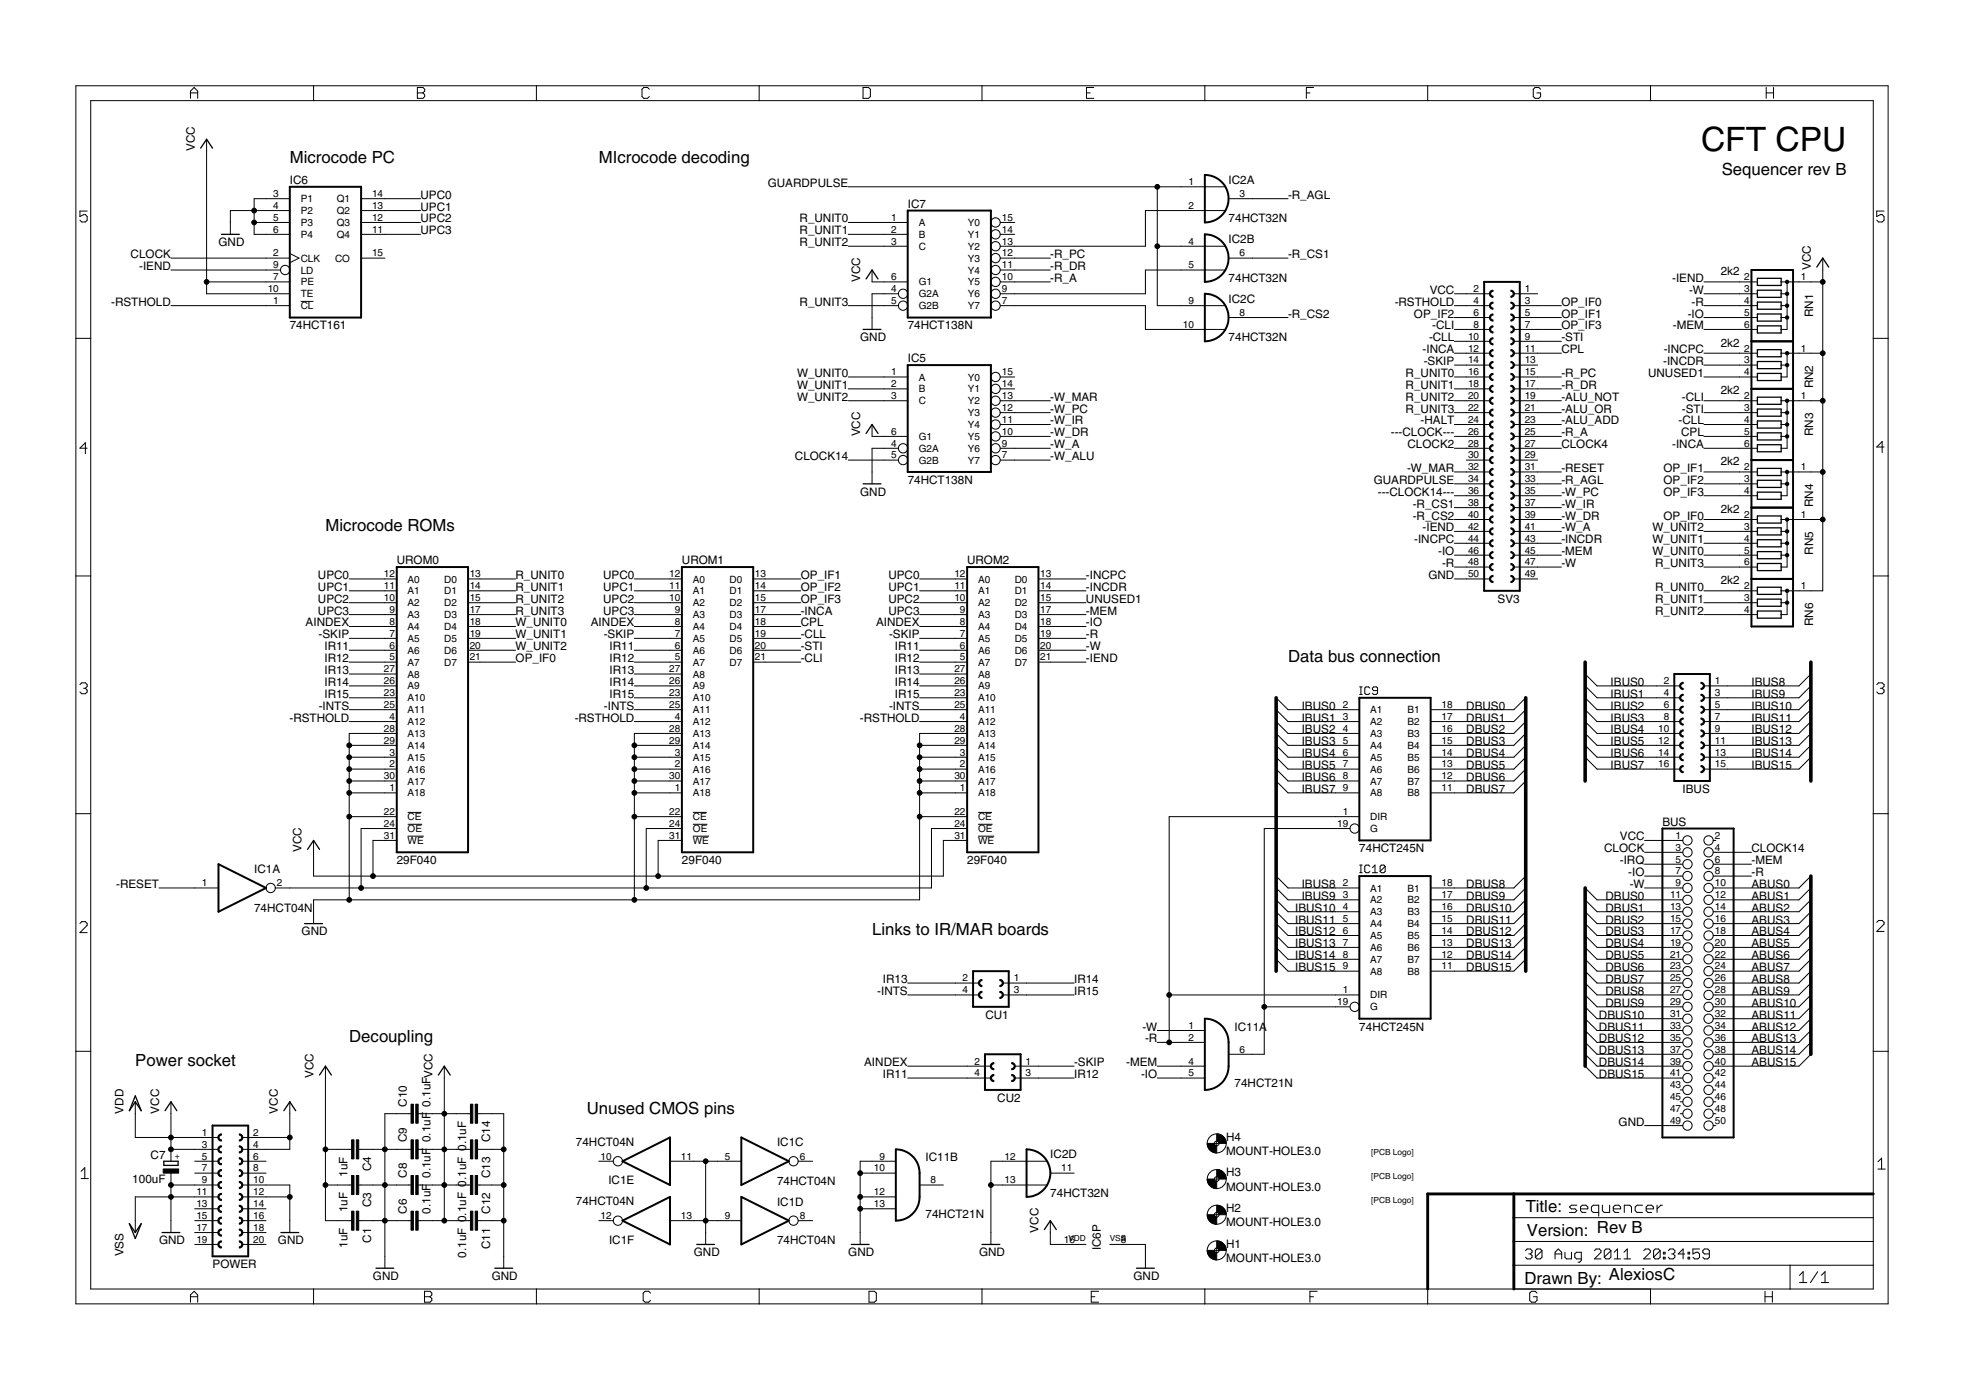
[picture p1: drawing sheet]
<svg xmlns="http://www.w3.org/2000/svg" width="420mm" height="297mm" viewBox="0 0 420 297" stroke-linecap="round" stroke-linejoin="round" font-family="sans-serif">
<defs><g id="words">
<text font-size="7.2" x="363.5" y="32.3">CFT CPU</text>
<g font-size="3.6">
<text x="61.9" y="34.8">Microcode PC</text>
<text x="128" y="34.8">MIcrocode decoding</text>
<text x="368" y="37.4">Sequencer rev B</text>
<text x="69.5" y="113.6">Microcode ROMs</text>
<text x="275.3" y="141.5">Data bus connection</text>
<text x="186.4" y="199.9">Links to IR/MAR boards</text>
<text x="28.9" y="227.8">Power socket</text>
<text x="74.6" y="222.8">Decoupling</text>
<text x="125.4" y="238">Unused CMOS pins</text>
<text x="326.1" y="259.1">Title:</text>
<text x="326.3" y="264.2">Version: Rev B</text>
<text x="325.8" y="274.3">Drawn By: AlexiosC</text>
</g>
<g font-size="2.5">
<text x="41.6" y="32.3" transform="rotate(-90 41.6 32.3)">VCC</text>
<text x="61.9" y="39.3">IC6</text>
<text x="164.1" y="39.9">GUARDPULSE</text>
<text x="262.6" y="39.3">IC2A</text>
<text x="89.9" y="42.5">UPC0</text>
<text x="89.9" y="45">UPC1</text>
<text x="89.9" y="47.5">UPC2</text>
<text x="170.9" y="47.5">R_UNIT0</text>
<text x="194" y="44.4">IC7</text>
<text x="262.6" y="47.5">74HCT32N</text>
<text x="275.3" y="42.5">-R_AGL</text>
<text x="46.7" y="52.6">GND</text>
<text x="89.9" y="50.1">UPC3</text>
<text x="170.9" y="50.1">R_UNIT1</text>
<text x="170.9" y="52.6">R_UNIT2</text>
<text x="262.6" y="52">IC2B</text>
<text x="27.9" y="55.2">CLOCK</text>
<text x="29.7" y="57.7">-IEND</text>
<text x="224.5" y="55.2">-R_PC</text>
<text x="224.5" y="57.7">-R_DR</text>
<text x="275.3" y="55.2">-R_CS1</text>
<text x="367.7" y="58.8">2k2</text>
<text x="387" y="57.7" transform="rotate(-90 387 57.7)">VCC</text>
<text x="23.8" y="65.3">-RSTHOLD</text>
<text x="170.9" y="65.3">R_UNIT3</text>
<text x="183.8" y="60.2" transform="rotate(-90 183.8 60.2)">VCC</text>
<text x="224.5" y="60.2">-R_A</text>
<text x="262.6" y="60.2">74HCT32N</text>
<text x="262.6" y="64.7">IC2C</text>
<text x="298.1" y="65.3">-RSTHOLD</text>
<text x="305.6" y="62.8">VCC</text>
<text x="333.7" y="65.3">OP_IF0</text>
<text x="357.4" y="60.2">-IEND</text>
<text x="361" y="62.8">-W</text>
<text x="361.5" y="65.3">-R</text>
<text x="61.9" y="70.4">74HCT161</text>
<text x="194" y="70.4">74HCT138N</text>
<text x="275.3" y="67.9">-R_CS2</text>
<text x="302.2" y="67.9">OP_IF2</text>
<text x="306.1" y="70.4">-CLI</text>
<text x="333.7" y="67.9">OP_IF1</text>
<text x="333.7" y="70.4">OP_IF3</text>
<text x="357.5" y="70.4">-MEM</text>
<text x="360.7" y="67.9">-IO</text>
<text x="387.5" y="67.8" transform="rotate(-90 387.5 67.8)">RN1</text>
<text x="183.8" y="72.9">GND</text>
<text x="194" y="77.4">IC5</text>
<text x="262.6" y="72.9">74HCT32N</text>
<text x="304" y="75.5">-INCA</text>
<text x="305.4" y="72.9">-CLL</text>
<text x="333.7" y="72.9">-STI</text>
<text x="333.7" y="75.5">CPL</text>
<text x="355.6" y="75.5">-INCPC</text>
<text x="367.7" y="74.1">2k2</text>
<text x="170.3" y="80.6">W_UNIT0</text>
<text x="170.3" y="83.1">W_UNIT1</text>
<text x="300.4" y="80.6">R_UNIT0</text>
<text x="300.4" y="83.1">R_UNIT1</text>
<text x="304.3" y="78">-SKIP</text>
<text x="333.7" y="80.6">-R_PC</text>
<text x="333.7" y="83.1">-R_DR</text>
<text x="352.2" y="80.6">UNUSED1</text>
<text x="355.4" y="78">-INCDR</text>
<text x="387.5" y="83" transform="rotate(-90 387.5 83)">RN2</text>
<text x="170.3" y="85.6">W_UNIT2</text>
<text x="224.5" y="85.6">-W_MAR</text>
<text x="224.5" y="88.2">-W_PC</text>
<text x="300.4" y="85.6">R_UNIT2</text>
<text x="300.4" y="88.2">R_UNIT3</text>
<text x="333.7" y="88.2">-ALU_OR</text>
<text x="333.7" y="85.6">-ALU_NOT</text>
<text x="359.4" y="85.6">-CLI</text>
<text x="359.4" y="88.2">-STI</text>
<text x="367.7" y="84.2">2k2</text>
<text x="183.8" y="93.2" transform="rotate(-90 183.8 93.2)">VCC</text>
<text x="224.5" y="90.7">-W_IR</text>
<text x="224.5" y="93.2">-W_DR</text>
<text x="224.5" y="95.8">-W_A</text>
<text x="297.3" y="93.2">---CLOCK---</text>
<text x="300.8" y="95.8">CLOCK2</text>
<text x="303.6" y="90.7">-HALT</text>
<text x="333.7" y="95.8">CLOCK4</text>
<text x="333.7" y="90.7">-ALU_ADD</text>
<text x="333.7" y="93.2">-R_A</text>
<text x="357.4" y="95.8">-INCA</text>
<text x="358.7" y="90.7">-CLL</text>
<text x="359.3" y="93.2">CPL</text>
<text x="387.5" y="93.2" transform="rotate(-90 387.5 93.2)">RN3</text>
<text x="169.9" y="98.3">CLOCK14</text>
<text x="224.5" y="98.3">-W_ALU</text>
<text x="300.7" y="100.9">-W_MAR</text>
<text x="333.7" y="100.9">-RESET</text>
<text x="355.5" y="100.9">OP_IF1</text>
<text x="367.7" y="99.5">2k2</text>
<text x="183.8" y="105.9">GND</text>
<text x="194" y="103.4">74HCT138N</text>
<text x="293.6" y="103.4">GUARDPULSE</text>
<text x="294.5" y="105.9">---CLOCK14---</text>
<text x="333.7" y="105.9">-W_PC</text>
<text x="333.7" y="103.4">-R_AGL</text>
<text x="355.5" y="103.4">OP_IF2</text>
<text x="355.5" y="105.9">OP_IF3</text>
<text x="301.9" y="108.5">-R_CS1</text>
<text x="301.9" y="111">-R_CS2</text>
<text x="304" y="113.6">-IEND</text>
<text x="333.7" y="108.5">-W_IR</text>
<text x="333.7" y="111">-W_DR</text>
<text x="333.7" y="113.6">-W_A</text>
<text x="353.2" y="113.6">W_UNIT2</text>
<text x="355.5" y="111">OP_IF0</text>
<text x="367.7" y="109.6">2k2</text>
<text x="387.5" y="108.4" transform="rotate(-90 387.5 108.4)">RN4</text>
<text x="302.2" y="116.1">-INCPC</text>
<text x="307.3" y="118.6">-IO</text>
<text x="333.7" y="118.6">-MEM</text>
<text x="333.7" y="116.1">-INCDR</text>
<text x="353.2" y="118.6">W_UNIT0</text>
<text x="353.2" y="116.1">W_UNIT1</text>
<text x="387.5" y="118.6" transform="rotate(-90 387.5 118.6)">RN5</text>
<text x="68" y="123.7">UPC0</text>
<text x="84.8" y="120.5">UROM0</text>
<text x="110.2" y="123.7">R_UNIT0</text>
<text x="128.9" y="123.7">UPC0</text>
<text x="145.7" y="120.5">UROM1</text>
<text x="171.1" y="123.7">OP_IF1</text>
<text x="189.9" y="123.7">UPC0</text>
<text x="206.7" y="120.5">UROM2</text>
<text x="232.1" y="123.7">-INCPC</text>
<text x="305.3" y="123.7">GND</text>
<text x="308.2" y="121.2">-R</text>
<text x="333.7" y="121.2">-W</text>
<text x="353.7" y="121.2">R_UNIT3</text>
<text x="367.7" y="124.9">2k2</text>
<text x="68" y="126.3">UPC1</text>
<text x="68" y="128.8">UPC2</text>
<text x="68" y="131.3">UPC3</text>
<text x="110.2" y="126.3">R_UNIT1</text>
<text x="110.2" y="128.8">R_UNIT2</text>
<text x="110.2" y="131.3">R_UNIT3</text>
<text x="128.9" y="126.3">UPC1</text>
<text x="128.9" y="128.8">UPC2</text>
<text x="128.9" y="131.3">UPC3</text>
<text x="171.1" y="131.3">-INCA</text>
<text x="171.1" y="126.3">OP_IF2</text>
<text x="171.1" y="128.8">OP_IF3</text>
<text x="189.9" y="126.3">UPC1</text>
<text x="189.9" y="128.8">UPC2</text>
<text x="189.9" y="131.3">UPC3</text>
<text x="232.1" y="131.3">-MEM</text>
<text x="232.1" y="126.3">-INCDR</text>
<text x="232.1" y="128.8">UNUSED1</text>
<text x="320" y="128.8">SV3</text>
<text x="353.7" y="126.3">R_UNIT0</text>
<text x="353.7" y="128.8">R_UNIT1</text>
<text x="353.7" y="131.3">R_UNIT2</text>
<text x="65.3" y="133.9">AINDEX</text>
<text x="68.1" y="136.4">-SKIP</text>
<text x="110.2" y="133.9">W_UNIT0</text>
<text x="110.2" y="136.4">W_UNIT1</text>
<text x="126.3" y="133.9">AINDEX</text>
<text x="129" y="136.4">-SKIP</text>
<text x="171.1" y="136.4">-CLL</text>
<text x="171.1" y="133.9">CPL</text>
<text x="187.2" y="133.9">AINDEX</text>
<text x="190" y="136.4">-SKIP</text>
<text x="232.1" y="133.9">-IO</text>
<text x="232.1" y="136.4">-R</text>
<text x="387.5" y="133.8" transform="rotate(-90 387.5 133.8)">RN6</text>
<text x="69.3" y="139">IR11</text>
<text x="69.3" y="141.5">IR12</text>
<text x="110.2" y="139">W_UNIT2</text>
<text x="110.2" y="141.5">OP_IF0</text>
<text x="130.3" y="139">IR11</text>
<text x="130.3" y="141.5">IR12</text>
<text x="171.1" y="141.5">-CLI</text>
<text x="171.1" y="139">-STI</text>
<text x="191.2" y="139">IR11</text>
<text x="191.2" y="141.5">IR12</text>
<text x="232.1" y="141.5">-IEND</text>
<text x="232.1" y="139">-W</text>
<text x="69.3" y="144">IR13</text>
<text x="69.3" y="146.6">IR14</text>
<text x="69.3" y="149.1">IR15</text>
<text x="130.3" y="144">IR13</text>
<text x="130.3" y="146.6">IR14</text>
<text x="130.3" y="149.1">IR15</text>
<text x="191.2" y="144">IR13</text>
<text x="191.2" y="146.6">IR14</text>
<text x="191.2" y="149.1">IR15</text>
<text x="344.2" y="146.6">IBUS0</text>
<text x="344.2" y="149.1">IBUS1</text>
<text x="374.3" y="146.6">IBUS8</text>
<text x="374.3" y="149.1">IBUS9</text>
<text x="61.9" y="154.2">-RSTHOLD</text>
<text x="68.1" y="151.7">-INTS</text>
<text x="122.8" y="154.2">-RSTHOLD</text>
<text x="129.1" y="151.7">-INTS</text>
<text x="183.8" y="154.2">-RSTHOLD</text>
<text x="190" y="151.7">-INTS</text>
<text x="278.2" y="151.7">IBUS0</text>
<text x="278.2" y="154.2">IBUS1</text>
<text x="313.4" y="151.7">DBUS0</text>
<text x="313.4" y="154.2">DBUS1</text>
<text x="344.2" y="151.7">IBUS2</text>
<text x="344.2" y="154.2">IBUS3</text>
<text x="374.3" y="151.7">IBUS10</text>
<text x="374.3" y="154.2">IBUS11</text>
<text x="278.2" y="156.7">IBUS2</text>
<text x="278.2" y="159.3">IBUS3</text>
<text x="278.2" y="161.8">IBUS4</text>
<text x="313.4" y="156.7">DBUS2</text>
<text x="313.4" y="159.3">DBUS3</text>
<text x="313.4" y="161.8">DBUS4</text>
<text x="344.2" y="156.7">IBUS4</text>
<text x="344.2" y="159.3">IBUS5</text>
<text x="344.2" y="161.8">IBUS6</text>
<text x="374.3" y="156.7">IBUS12</text>
<text x="374.3" y="159.3">IBUS13</text>
<text x="374.3" y="161.8">IBUS14</text>
<text x="278.2" y="164.4">IBUS5</text>
<text x="278.2" y="166.9">IBUS6</text>
<text x="313.4" y="164.4">DBUS5</text>
<text x="313.4" y="166.9">DBUS6</text>
<text x="344.2" y="164.4">IBUS7</text>
<text x="374.3" y="164.4">IBUS15</text>
<text x="278.2" y="169.4">IBUS7</text>
<text x="313.4" y="169.4">DBUS7</text>
<text x="359.6" y="169.4">IBUS</text>
<text x="346.2" y="179.6">VCC</text>
<text x="355.3" y="176.4">BUS</text>
<text x="64.5" y="182.1" transform="rotate(-90 64.5 182.1)">VCC</text>
<text x="84.8" y="184.7">29F040</text>
<text x="145.7" y="184.7">29F040</text>
<text x="206.7" y="184.7">29F040</text>
<text x="290.5" y="182.1">74HCT245N</text>
<text x="342.8" y="182.1">CLOCK</text>
<text x="346.2" y="184.7">-IRQ</text>
<text x="374.3" y="182.1">CLOCK14</text>
<text x="374.3" y="184.7">-MEM</text>
<text x="24.8" y="189.8">-RESET</text>
<text x="54.3" y="186.6">IC1A</text>
<text x="278.2" y="189.8">IBUS8</text>
<text x="313.4" y="189.8">DBUS8</text>
<text x="348" y="187.2">-IO</text>
<text x="348.3" y="189.8">-W</text>
<text x="374.3" y="187.2">-R</text>
<text x="374.3" y="189.8">ABUS0</text>
<text x="54.3" y="194.8">74HCT04N</text>
<text x="276.8" y="194.8">IBUS10</text>
<text x="276.8" y="197.4">IBUS11</text>
<text x="278.2" y="192.3">IBUS9</text>
<text x="313.4" y="192.3">DBUS9</text>
<text x="313.4" y="194.8">DBUS10</text>
<text x="313.4" y="197.4">DBUS11</text>
<text x="343.1" y="192.3">DBUS0</text>
<text x="343.1" y="194.8">DBUS1</text>
<text x="343.1" y="197.4">DBUS2</text>
<text x="374.3" y="192.3">ABUS1</text>
<text x="374.3" y="194.8">ABUS2</text>
<text x="374.3" y="197.4">ABUS3</text>
<text x="64.5" y="199.9">GND</text>
<text x="276.8" y="199.9">IBUS12</text>
<text x="276.8" y="202.4">IBUS13</text>
<text x="313.4" y="199.9">DBUS12</text>
<text x="313.4" y="202.4">DBUS13</text>
<text x="343.1" y="199.9">DBUS3</text>
<text x="343.1" y="202.4">DBUS4</text>
<text x="374.3" y="199.9">ABUS4</text>
<text x="374.3" y="202.4">ABUS5</text>
<text x="276.8" y="205">IBUS14</text>
<text x="276.8" y="207.5">IBUS15</text>
<text x="313.4" y="205">DBUS14</text>
<text x="313.4" y="207.5">DBUS15</text>
<text x="343.1" y="205">DBUS5</text>
<text x="343.1" y="207.5">DBUS6</text>
<text x="374.3" y="205">ABUS6</text>
<text x="374.3" y="207.5">ABUS7</text>
<text x="187.5" y="212.6">-INTS</text>
<text x="188.7" y="210.1">IR13</text>
<text x="229.5" y="210.1">IR14</text>
<text x="229.5" y="212.6">IR15</text>
<text x="343.1" y="210.1">DBUS7</text>
<text x="343.1" y="212.6">DBUS8</text>
<text x="343.1" y="215.1">DBUS9</text>
<text x="374.3" y="210.1">ABUS8</text>
<text x="374.3" y="212.6">ABUS9</text>
<text x="374.3" y="215.1">ABUS10</text>
<text x="210.6" y="217.7">CU1</text>
<text x="244.2" y="220.2">-W</text>
<text x="263.8" y="220.2">IC11A</text>
<text x="290.5" y="220.2">74HCT245N</text>
<text x="341.7" y="217.7">DBUS10</text>
<text x="341.7" y="220.2">DBUS11</text>
<text x="374.3" y="217.7">ABUS11</text>
<text x="374.3" y="220.2">ABUS12</text>
<text x="184.7" y="227.8">AINDEX</text>
<text x="229.5" y="227.8">-SKIP</text>
<text x="240.7" y="227.8">-MEM</text>
<text x="244.7" y="222.8">-R</text>
<text x="341.7" y="222.8">DBUS12</text>
<text x="341.7" y="225.3">DBUS13</text>
<text x="341.7" y="227.8">DBUS14</text>
<text x="374.3" y="225.3">ABUS14</text>
<text x="374.3" y="227.8">ABUS15</text>
<text x="374.3" y="222.8">ABUS13</text>
<text x="67" y="230.4" transform="rotate(-90 67 230.4)">VCC</text>
<text x="188.7" y="230.4">IR11</text>
<text x="229.5" y="230.4">IR12</text>
<text x="243.9" y="230.4">-IO</text>
<text x="263.8" y="232.3">74HCT21N</text>
<text x="341.7" y="230.4">DBUS15</text>
<text x="26.4" y="238" transform="rotate(-90 26.4 238)">VDD</text>
<text x="34" y="238" transform="rotate(-90 34 238)">VCC</text>
<text x="59.4" y="238" transform="rotate(-90 59.4 238)">VCC</text>
<text x="86.9" y="236.5" transform="rotate(-90 86.9 236.5)">C10</text>
<text x="92" y="236.5" transform="rotate(-90 92 236.5)">0.1uFVCC</text>
<text x="213.1" y="235.5">CU2</text>
<text x="86.9" y="244.1" transform="rotate(-90 86.9 244.1)">C9</text>
<text x="92" y="244.1" transform="rotate(-90 92 244.1)">0.1uF</text>
<text x="104.7" y="244.1" transform="rotate(-90 104.7 244.1)">C14</text>
<text x="123.1" y="244.9">74HCT04N</text>
<text x="166.1" y="245">IC1C</text>
<text x="262.1" y="243.8">H4</text>
<text x="345.9" y="240.5">GND</text>
<text x="32.2" y="247.7">C7</text>
<text x="74.2" y="251.5" transform="rotate(-90 74.2 251.5)">1uF</text>
<text x="79.3" y="250.3" transform="rotate(-90 79.3 250.3)">C4</text>
<text x="86.9" y="251.7" transform="rotate(-90 86.9 251.7)">C8</text>
<text x="92" y="251.7" transform="rotate(-90 92 251.7)">0.1uF</text>
<text x="104.7" y="251.7" transform="rotate(-90 104.7 251.7)">C13</text>
<text x="197.8" y="248.2">IC11B</text>
<text x="224.5" y="247.5">IC2D</text>
<text x="262.1" y="246.8">MOUNT-HOLE3.0</text>
<text x="262.1" y="251.4">H3</text>
<text x="28.3" y="252.8">100uF</text>
<text x="79.3" y="258" transform="rotate(-90 79.3 258)">C3</text>
<text x="123.1" y="257.6">74HCT04N</text>
<text x="130" y="253.1">IC1E</text>
<text x="166.1" y="253.2">74HCT04N</text>
<text x="166.1" y="257.7">IC1D</text>
<text x="224.5" y="255.8">74HCT32N</text>
<text x="262.1" y="254.4">MOUNT-HOLE3.0</text>
<text x="74.2" y="259.1" transform="rotate(-90 74.2 259.1)">1uF</text>
<text x="86.9" y="259.3" transform="rotate(-90 86.9 259.3)">C6</text>
<text x="92" y="259.3" transform="rotate(-90 92 259.3)">0.1uF</text>
<text x="104.7" y="259.4" transform="rotate(-90 104.7 259.4)">C12</text>
<text x="197.8" y="260.2">74HCT21N</text>
<text x="221.9" y="263.4" transform="rotate(-90 221.9 263.4)">VCC</text>
<text x="262.1" y="262">MOUNT-HOLE3.0</text>
<text x="262.1" y="259">H2</text>
<text x="26.4" y="268.5" transform="rotate(-90 26.4 268.5)">VSS</text>
<text x="34" y="265.9">GND</text>
<text x="59.4" y="265.9">GND</text>
<text x="74.2" y="266.7" transform="rotate(-90 74.2 266.7)">1uF</text>
<text x="79.3" y="265.6" transform="rotate(-90 79.3 265.6)">C1</text>
<text x="99.6" y="268.8" transform="rotate(-90 99.6 268.8)">0.1uF 0.1uF 0.1uF 0.1uF</text>
<text x="104.7" y="267" transform="rotate(-90 104.7 267)">C11</text>
<text x="130.2" y="265.8">IC1F</text>
<text x="148.3" y="268.5">GND</text>
<text x="166.1" y="265.9">74HCT04N</text>
<text x="181.3" y="268.5">GND</text>
<text x="209.2" y="268.5">GND</text>
<text x="235.3" y="267.2" transform="rotate(-90 235.3 267.2)">IC6P</text>
<text x="262.1" y="269.7">MOUNT-HOLE3.0</text>
<text x="262.1" y="266.6">H1</text>
<text x="45.4" y="271">POWER</text>
<text x="79.7" y="273.6">GND</text>
<text x="105.1" y="273.6">GND</text>
<text x="242.2" y="273.6">GND</text>
</g>
<g font-size="2.1">
<text x="254" y="39.6">1</text>
<text x="58.4" y="42.1">3</text>
<text x="58.4" y="44.6">4</text>
<text x="58.4" y="47.2">5</text>
<text x="64.3" y="43.2">P1</text>
<text x="64.3" y="45.8">P2</text>
<text x="72" y="45.8">Q2</text>
<text x="72" y="43.2">Q1</text>
<text x="79.5" y="47.2">12</text>
<text x="79.5" y="44.6">13</text>
<text x="79.5" y="42.1">14</text>
<text x="190.5" y="47.2">1</text>
<text x="214.1" y="47.2">15</text>
<text x="254" y="44.6">2</text>
<text x="264.9" y="42.1">3</text>
<text x="58.4" y="49.7">6</text>
<text x="64.3" y="48.3">P3</text>
<text x="64.3" y="50.8">P4</text>
<text x="72" y="50.8">Q4</text>
<text x="72" y="48.3">Q3</text>
<text x="79.5" y="49.7">11</text>
<text x="190.5" y="49.7">2</text>
<text x="190.5" y="52.3">3</text>
<text x="196.3" y="48.3">A</text>
<text x="196.3" y="50.8">B</text>
<text x="196.3" y="53.4">C</text>
<text x="206.8" y="53.4">Y2</text>
<text x="206.8" y="50.8">Y1</text>
<text x="206.8" y="48.3">Y0</text>
<text x="214.1" y="52.3">13</text>
<text x="214.1" y="49.7">14</text>
<text x="254" y="52.3">4</text>
<text x="58.4" y="54.8">2</text>
<text x="58.4" y="59.9">7</text>
<text x="58.4" y="57.3">9</text>
<text x="64.3" y="55.9">CLK</text>
<text x="64.3" y="58.5">LD</text>
<text x="71.6" y="55.9">CO</text>
<text x="79.5" y="54.8">15</text>
<text x="190.5" y="59.9">6</text>
<text x="206.8" y="58.5">Y4</text>
<text x="206.8" y="55.9">Y3</text>
<text x="214.1" y="59.9">10</text>
<text x="214.1" y="57.3">11</text>
<text x="214.1" y="54.8">12</text>
<text x="254" y="57.3">5</text>
<text x="264.9" y="54.8">6</text>
<text x="372.8" y="59.9">2</text>
<text x="384.8" y="59.9">1</text>
<text x="57.2" y="62.4">10</text>
<text x="58.4" y="65">1</text>
<text x="64.3" y="61">PE</text>
<text x="64.3" y="63.5">TE</text>
<text x="190.5" y="62.4">4</text>
<text x="190.5" y="65">5</text>
<text x="196.3" y="63.5">G2A</text>
<text x="196.3" y="61">G1</text>
<text x="206.8" y="63.5">Y6</text>
<text x="206.8" y="61">Y5</text>
<text x="214.1" y="65">7</text>
<text x="214.1" y="62.4">9</text>
<text x="254" y="65">9</text>
<text x="314.9" y="62.4">2</text>
<text x="314.9" y="65">4</text>
<text x="325.9" y="62.4">1</text>
<text x="325.9" y="65">3</text>
<text x="372.8" y="62.4">3</text>
<text x="372.8" y="65">4</text>
<text x="64.3" y="66.1">CL</text>
<text x="196.3" y="66.1">G2B</text>
<text x="206.8" y="66.1">Y7</text>
<text x="252.8" y="70">10</text>
<text x="264.9" y="67.5">8</text>
<text x="314.9" y="67.5">6</text>
<text x="314.9" y="70">8</text>
<text x="325.9" y="67.5">5</text>
<text x="325.9" y="70">7</text>
<text x="372.8" y="67.5">5</text>
<text x="372.8" y="70">6</text>
<text x="313.7" y="72.6">10</text>
<text x="313.7" y="75.1">12</text>
<text x="313.7" y="77.7">14</text>
<text x="325.9" y="72.6">9</text>
<text x="325.9" y="75.1">11</text>
<text x="325.9" y="77.7">13</text>
<text x="372.8" y="75.1">2</text>
<text x="372.8" y="77.7">3</text>
<text x="384.8" y="75.1">1</text>
<text x="190.5" y="80.2">1</text>
<text x="190.5" y="82.7">2</text>
<text x="196.3" y="81.3">A</text>
<text x="196.3" y="83.9">B</text>
<text x="206.8" y="83.9">Y1</text>
<text x="206.8" y="81.3">Y0</text>
<text x="214.1" y="82.7">14</text>
<text x="214.1" y="80.2">15</text>
<text x="313.7" y="80.2">16</text>
<text x="313.7" y="82.7">18</text>
<text x="325.9" y="80.2">15</text>
<text x="325.9" y="82.7">17</text>
<text x="372.8" y="80.2">4</text>
<text x="190.5" y="85.3">3</text>
<text x="196.3" y="86.4">C</text>
<text x="206.8" y="88.9">Y3</text>
<text x="206.8" y="86.4">Y2</text>
<text x="214.1" y="87.8">12</text>
<text x="214.1" y="85.3">13</text>
<text x="313.7" y="85.3">20</text>
<text x="313.7" y="87.8">22</text>
<text x="325.9" y="85.3">19</text>
<text x="325.9" y="87.8">21</text>
<text x="372.8" y="85.3">2</text>
<text x="372.8" y="87.8">3</text>
<text x="384.8" y="85.3">1</text>
<text x="190.5" y="95.4">4</text>
<text x="190.5" y="92.9">6</text>
<text x="196.3" y="94">G1</text>
<text x="206.8" y="94">Y5</text>
<text x="206.8" y="91.5">Y4</text>
<text x="214.1" y="95.4">9</text>
<text x="214.1" y="92.9">10</text>
<text x="214.1" y="90.4">11</text>
<text x="313.7" y="90.4">24</text>
<text x="313.7" y="92.9">26</text>
<text x="313.7" y="95.4">28</text>
<text x="325.9" y="90.4">23</text>
<text x="325.9" y="92.9">25</text>
<text x="325.9" y="95.4">27</text>
<text x="372.8" y="90.4">4</text>
<text x="372.8" y="92.9">5</text>
<text x="372.8" y="95.4">6</text>
<text x="190.5" y="98">5</text>
<text x="196.3" y="96.5">G2A</text>
<text x="196.3" y="99.1">G2B</text>
<text x="206.8" y="99.1">Y7</text>
<text x="206.8" y="96.6">Y6</text>
<text x="214.1" y="98">7</text>
<text x="313.7" y="98">30</text>
<text x="313.7" y="100.5">32</text>
<text x="325.9" y="98">29</text>
<text x="325.9" y="100.5">31</text>
<text x="372.8" y="100.5">2</text>
<text x="384.8" y="100.5">1</text>
<text x="313.7" y="103.1">34</text>
<text x="313.7" y="105.6">36</text>
<text x="325.9" y="103.1">33</text>
<text x="325.9" y="105.6">35</text>
<text x="372.8" y="103.1">3</text>
<text x="372.8" y="105.6">4</text>
<text x="313.7" y="108.1">38</text>
<text x="313.7" y="110.7">40</text>
<text x="313.7" y="113.2">42</text>
<text x="325.9" y="108.1">37</text>
<text x="325.9" y="110.7">39</text>
<text x="325.9" y="113.2">41</text>
<text x="372.8" y="110.7">2</text>
<text x="372.8" y="113.2">3</text>
<text x="384.8" y="110.7">1</text>
<text x="313.7" y="115.7">44</text>
<text x="313.7" y="118.3">46</text>
<text x="325.9" y="115.7">43</text>
<text x="325.9" y="118.3">45</text>
<text x="372.8" y="115.7">4</text>
<text x="372.8" y="118.3">5</text>
<text x="82.1" y="125.9">11</text>
<text x="82.1" y="123.4">12</text>
<text x="87.1" y="124.5">A0</text>
<text x="95" y="124.5">D0</text>
<text x="100.4" y="123.4">13</text>
<text x="100.4" y="125.9">14</text>
<text x="143" y="125.9">11</text>
<text x="143" y="123.4">12</text>
<text x="148.1" y="124.5">A0</text>
<text x="155.9" y="124.5">D0</text>
<text x="161.3" y="123.4">13</text>
<text x="161.3" y="125.9">14</text>
<text x="204" y="125.9">11</text>
<text x="204" y="123.4">12</text>
<text x="209" y="124.5">A0</text>
<text x="216.9" y="124.5">D0</text>
<text x="222.3" y="123.4">13</text>
<text x="222.3" y="125.9">14</text>
<text x="313.7" y="120.8">48</text>
<text x="313.7" y="123.4">50</text>
<text x="325.9" y="120.8">47</text>
<text x="325.9" y="123.4">49</text>
<text x="372.8" y="120.8">6</text>
<text x="372.8" y="125.9">2</text>
<text x="384.8" y="125.9">1</text>
<text x="82.1" y="128.4">10</text>
<text x="83.2" y="131">9</text>
<text x="87.1" y="129.6">A2</text>
<text x="87.1" y="127">A1</text>
<text x="95" y="127">D1</text>
<text x="95" y="129.6">D2</text>
<text x="100.4" y="128.4">15</text>
<text x="100.4" y="131">17</text>
<text x="143" y="128.4">10</text>
<text x="144.2" y="131">9</text>
<text x="148.1" y="129.6">A2</text>
<text x="148.1" y="127">A1</text>
<text x="155.9" y="127">D1</text>
<text x="155.9" y="129.6">D2</text>
<text x="161.3" y="128.4">15</text>
<text x="161.3" y="131">17</text>
<text x="204" y="128.4">10</text>
<text x="205.2" y="131">9</text>
<text x="209" y="129.6">A2</text>
<text x="209" y="127">A1</text>
<text x="216.9" y="127">D1</text>
<text x="216.9" y="129.6">D2</text>
<text x="222.3" y="128.4">15</text>
<text x="222.3" y="131">17</text>
<text x="372.8" y="128.4">3</text>
<text x="372.8" y="131">4</text>
<text x="83.2" y="136.1">7</text>
<text x="83.2" y="133.5">8</text>
<text x="87.1" y="137.2">A5</text>
<text x="87.1" y="134.6">A4</text>
<text x="87.1" y="132.1">A3</text>
<text x="95" y="132.1">D3</text>
<text x="95" y="134.6">D4</text>
<text x="95" y="137.2">D5</text>
<text x="100.4" y="133.5">18</text>
<text x="100.4" y="136.1">19</text>
<text x="144.2" y="136.1">7</text>
<text x="144.2" y="133.5">8</text>
<text x="148.1" y="137.2">A5</text>
<text x="148.1" y="134.6">A4</text>
<text x="148.1" y="132.1">A3</text>
<text x="155.9" y="132.1">D3</text>
<text x="155.9" y="134.6">D4</text>
<text x="155.9" y="137.2">D5</text>
<text x="161.3" y="133.5">18</text>
<text x="161.3" y="136.1">19</text>
<text x="205.2" y="136.1">7</text>
<text x="205.2" y="133.5">8</text>
<text x="209" y="137.2">A5</text>
<text x="209" y="134.6">A4</text>
<text x="209" y="132.1">A3</text>
<text x="216.9" y="132.1">D3</text>
<text x="216.9" y="134.6">D4</text>
<text x="216.9" y="137.2">D5</text>
<text x="222.3" y="133.5">18</text>
<text x="222.3" y="136.1">19</text>
<text x="82.1" y="143.7">27</text>
<text x="83.2" y="141.1">5</text>
<text x="83.2" y="138.6">6</text>
<text x="87.1" y="142.3">A7</text>
<text x="87.1" y="139.7">A6</text>
<text x="95" y="139.7">D6</text>
<text x="95" y="142.3">D7</text>
<text x="100.4" y="138.6">20</text>
<text x="100.4" y="141.1">21</text>
<text x="143" y="143.7">27</text>
<text x="144.2" y="141.1">5</text>
<text x="144.2" y="138.6">6</text>
<text x="148.1" y="142.3">A7</text>
<text x="148.1" y="139.7">A6</text>
<text x="155.9" y="139.7">D6</text>
<text x="155.9" y="142.3">D7</text>
<text x="161.3" y="138.6">20</text>
<text x="161.3" y="141.1">21</text>
<text x="204" y="143.7">27</text>
<text x="205.2" y="141.1">5</text>
<text x="205.2" y="138.6">6</text>
<text x="209" y="142.3">A7</text>
<text x="209" y="139.7">A6</text>
<text x="216.9" y="139.7">D6</text>
<text x="216.9" y="142.3">D7</text>
<text x="222.3" y="138.6">20</text>
<text x="222.3" y="141.1">21</text>
<text x="82.1" y="148.8">23</text>
<text x="82.1" y="146.2">26</text>
<text x="87.1" y="149.9">A10</text>
<text x="87.1" y="147.3">A9</text>
<text x="87.1" y="144.8">A8</text>
<text x="143" y="148.8">23</text>
<text x="143" y="146.2">26</text>
<text x="148.1" y="149.9">A10</text>
<text x="148.1" y="147.3">A9</text>
<text x="148.1" y="144.8">A8</text>
<text x="204" y="148.8">23</text>
<text x="204" y="146.2">26</text>
<text x="209" y="149.9">A10</text>
<text x="209" y="147.3">A9</text>
<text x="209" y="144.8">A8</text>
<text x="355.6" y="146.2">2</text>
<text x="355.6" y="148.8">4</text>
<text x="366.5" y="146.2">1</text>
<text x="366.5" y="148.8">3</text>
<text x="82.1" y="151.3">25</text>
<text x="83.2" y="153.8">4</text>
<text x="87.1" y="155">A12</text>
<text x="87.1" y="152.4">A11</text>
<text x="143" y="151.3">25</text>
<text x="144.2" y="153.8">4</text>
<text x="148.1" y="155">A12</text>
<text x="148.1" y="152.4">A11</text>
<text x="204" y="151.3">25</text>
<text x="205.2" y="153.8">4</text>
<text x="209" y="155">A12</text>
<text x="209" y="152.4">A11</text>
<text x="287" y="151.3">2</text>
<text x="287" y="153.8">3</text>
<text x="292.8" y="152.4">A1</text>
<text x="292.8" y="155">A2</text>
<text x="300.8" y="155">B2</text>
<text x="300.8" y="152.4">B1</text>
<text x="308.1" y="153.8">17</text>
<text x="308.1" y="151.3">18</text>
<text x="355.6" y="151.3">6</text>
<text x="355.6" y="153.8">8</text>
<text x="366.5" y="151.3">5</text>
<text x="366.5" y="153.8">7</text>
<text x="82.1" y="156.4">28</text>
<text x="82.1" y="158.9">29</text>
<text x="83.2" y="161.5">3</text>
<text x="87.1" y="157.5">A13</text>
<text x="87.1" y="160">A14</text>
<text x="143" y="156.4">28</text>
<text x="143" y="158.9">29</text>
<text x="144.2" y="161.5">3</text>
<text x="148.1" y="157.5">A13</text>
<text x="148.1" y="160">A14</text>
<text x="204" y="156.4">28</text>
<text x="204" y="158.9">29</text>
<text x="205.2" y="161.5">3</text>
<text x="209" y="157.5">A13</text>
<text x="209" y="160">A14</text>
<text x="287" y="156.4">4</text>
<text x="287" y="158.9">5</text>
<text x="287" y="161.5">6</text>
<text x="292.8" y="157.5">A3</text>
<text x="292.8" y="160">A4</text>
<text x="300.8" y="160">B4</text>
<text x="300.8" y="157.5">B3</text>
<text x="308.1" y="161.5">14</text>
<text x="308.1" y="158.9">15</text>
<text x="308.1" y="156.4">16</text>
<text x="354.4" y="156.4">10</text>
<text x="354.4" y="158.9">12</text>
<text x="354.4" y="161.5">14</text>
<text x="366.5" y="156.4">9</text>
<text x="366.5" y="158.9">11</text>
<text x="366.5" y="161.5">13</text>
<text x="82.1" y="166.5">30</text>
<text x="83.2" y="164">2</text>
<text x="87.1" y="162.6">A15</text>
<text x="87.1" y="165.1">A16</text>
<text x="87.1" y="167.7">A17</text>
<text x="143" y="166.5">30</text>
<text x="144.2" y="164">2</text>
<text x="148.1" y="162.6">A15</text>
<text x="148.1" y="165.1">A16</text>
<text x="148.1" y="167.7">A17</text>
<text x="204" y="166.5">30</text>
<text x="205.2" y="164">2</text>
<text x="209" y="162.6">A15</text>
<text x="209" y="165.1">A16</text>
<text x="209" y="167.7">A17</text>
<text x="287" y="164">7</text>
<text x="287" y="166.5">8</text>
<text x="292.8" y="162.6">A5</text>
<text x="292.8" y="165.1">A6</text>
<text x="292.8" y="167.7">A7</text>
<text x="300.8" y="167.7">B7</text>
<text x="300.8" y="165.1">B6</text>
<text x="300.8" y="162.6">B5</text>
<text x="308.1" y="166.5">12</text>
<text x="308.1" y="164">13</text>
<text x="354.4" y="164">16</text>
<text x="366.5" y="164">15</text>
<text x="83.2" y="169.1">1</text>
<text x="87.1" y="170.2">A18</text>
<text x="144.2" y="169.1">1</text>
<text x="148.1" y="170.2">A18</text>
<text x="205.2" y="169.1">1</text>
<text x="209" y="170.2">A18</text>
<text x="287" y="169.1">9</text>
<text x="292.8" y="170.2">A8</text>
<text x="300.8" y="170.2">B8</text>
<text x="308.1" y="169.1">11</text>
<text x="82.1" y="179.2">31</text>
<text x="82.1" y="174.2">22</text>
<text x="82.1" y="176.7">24</text>
<text x="87.1" y="175.3">CE</text>
<text x="87.1" y="177.8">OE</text>
<text x="143" y="179.2">31</text>
<text x="143" y="174.2">22</text>
<text x="143" y="176.7">24</text>
<text x="148.1" y="175.3">CE</text>
<text x="148.1" y="177.8">OE</text>
<text x="204" y="179.2">31</text>
<text x="204" y="174.2">22</text>
<text x="204" y="176.7">24</text>
<text x="209" y="175.3">CE</text>
<text x="209" y="177.8">OE</text>
<text x="285.8" y="176.7">19</text>
<text x="287" y="174.2">1</text>
<text x="292.8" y="175.3">DIR</text>
<text x="292.8" y="177.8">G</text>
<text x="358.1" y="179.2">1</text>
<text x="366.5" y="179.2">2</text>
<text x="87.1" y="180.4">WE</text>
<text x="148.1" y="180.4">WE</text>
<text x="209" y="180.4">WE</text>
<text x="358.1" y="181.8">3</text>
<text x="358.1" y="184.3">5</text>
<text x="366.5" y="181.8">4</text>
<text x="366.5" y="184.3">6</text>
<text x="43.2" y="189.4">1</text>
<text x="59.2" y="189.4">2</text>
<text x="287" y="189.4">2</text>
<text x="287" y="191.9">3</text>
<text x="292.8" y="190.5">A1</text>
<text x="300.8" y="190.5">B1</text>
<text x="308.1" y="191.9">17</text>
<text x="308.1" y="189.4">18</text>
<text x="356.9" y="191.9">11</text>
<text x="358.1" y="186.9">7</text>
<text x="358.1" y="189.4">9</text>
<text x="366.5" y="186.9">8</text>
<text x="366.5" y="189.4">10</text>
<text x="366.5" y="191.9">12</text>
<text x="287" y="194.5">4</text>
<text x="287" y="197">5</text>
<text x="292.8" y="193.1">A2</text>
<text x="292.8" y="195.6">A3</text>
<text x="300.8" y="195.6">B3</text>
<text x="300.8" y="193.1">B2</text>
<text x="308.1" y="197">15</text>
<text x="308.1" y="194.5">16</text>
<text x="356.9" y="194.5">13</text>
<text x="356.9" y="197">15</text>
<text x="366.5" y="194.5">14</text>
<text x="366.5" y="197">16</text>
<text x="287" y="199.6">6</text>
<text x="287" y="202.1">7</text>
<text x="292.8" y="198.1">A4</text>
<text x="292.8" y="200.7">A5</text>
<text x="292.8" y="203.2">A6</text>
<text x="300.8" y="203.2">B6</text>
<text x="300.8" y="200.7">B5</text>
<text x="300.8" y="198.1">B4</text>
<text x="308.1" y="202.1">13</text>
<text x="308.1" y="199.6">14</text>
<text x="356.9" y="199.6">17</text>
<text x="356.9" y="202.1">19</text>
<text x="366.5" y="199.6">18</text>
<text x="366.5" y="202.1">20</text>
<text x="205.7" y="209.7">2</text>
<text x="216.6" y="209.7">1</text>
<text x="287" y="204.6">8</text>
<text x="287" y="207.2">9</text>
<text x="292.8" y="205.7">A7</text>
<text x="292.8" y="208.3">A8</text>
<text x="300.8" y="208.3">B8</text>
<text x="300.8" y="205.7">B7</text>
<text x="308.1" y="207.2">11</text>
<text x="308.1" y="204.6">12</text>
<text x="356.9" y="204.6">21</text>
<text x="356.9" y="207.2">23</text>
<text x="356.9" y="209.7">25</text>
<text x="366.5" y="204.6">22</text>
<text x="366.5" y="207.2">24</text>
<text x="366.5" y="209.7">26</text>
<text x="205.7" y="212.2">4</text>
<text x="216.6" y="212.2">3</text>
<text x="285.8" y="214.8">19</text>
<text x="287" y="212.2">1</text>
<text x="292.8" y="213.4">DIR</text>
<text x="292.8" y="215.9">G</text>
<text x="356.9" y="212.2">27</text>
<text x="356.9" y="214.8">29</text>
<text x="366.5" y="212.2">28</text>
<text x="366.5" y="214.8">30</text>
<text x="254" y="219.9">1</text>
<text x="356.9" y="217.3">31</text>
<text x="356.9" y="219.9">33</text>
<text x="366.5" y="217.3">32</text>
<text x="366.5" y="219.9">34</text>
<text x="208.3" y="227.5">2</text>
<text x="219.2" y="227.5">1</text>
<text x="254" y="222.4">2</text>
<text x="254" y="227.5">4</text>
<text x="264.9" y="224.9">6</text>
<text x="356.9" y="222.4">35</text>
<text x="356.9" y="224.9">37</text>
<text x="356.9" y="227.5">39</text>
<text x="366.5" y="222.4">36</text>
<text x="366.5" y="224.9">38</text>
<text x="366.5" y="227.5">40</text>
<text x="208.3" y="230">4</text>
<text x="219.2" y="230">3</text>
<text x="254" y="230">5</text>
<text x="356.9" y="230">41</text>
<text x="356.9" y="232.6">43</text>
<text x="366.5" y="230">42</text>
<text x="366.5" y="232.6">44</text>
<text x="356.9" y="235.1">45</text>
<text x="356.9" y="237.6">47</text>
<text x="366.5" y="235.1">46</text>
<text x="366.5" y="237.6">48</text>
<text x="43.2" y="242.7">1</text>
<text x="43.2" y="245.3">3</text>
<text x="54.1" y="242.7">2</text>
<text x="54.1" y="245.3">4</text>
<text x="356.9" y="240.2">49</text>
<text x="366.5" y="240.2">50</text>
<text x="43.2" y="247.8">5</text>
<text x="43.2" y="250.3">7</text>
<text x="54.1" y="247.8">6</text>
<text x="54.1" y="250.3">8</text>
<text x="128.3" y="247.8">10</text>
<text x="145.5" y="247.8">11</text>
<text x="154.9" y="247.8">5</text>
<text x="170.9" y="247.8">6</text>
<text x="186.7" y="250.3">10</text>
<text x="187.9" y="247.8">9</text>
<text x="214.7" y="247.8">12</text>
<text x="226.8" y="250.3">11</text>
<text x="42" y="255.4">11</text>
<text x="42" y="258">13</text>
<text x="43.2" y="252.9">9</text>
<text x="54.1" y="252.9">10</text>
<text x="54.1" y="255.4">12</text>
<text x="54.1" y="258">14</text>
<text x="186.7" y="255.4">12</text>
<text x="186.7" y="258">13</text>
<text x="198.9" y="252.9">8</text>
<text x="214.7" y="252.9">13</text>
<text x="42" y="260.5">15</text>
<text x="42" y="263">17</text>
<text x="54.1" y="260.5">16</text>
<text x="54.1" y="263">18</text>
<text x="128.3" y="260.5">12</text>
<text x="145.5" y="260.5">13</text>
<text x="154.9" y="260.5">9</text>
<text x="170.9" y="260.5">8</text>
<text x="42" y="265.6">19</text>
<text x="54.1" y="265.6">20</text>
<text x="227.4" y="265.6">16</text>
<text x="239.5" y="265.6">8</text>
</g>
<g font-size="1.8">
<text x="38.4" y="247.8" transform="rotate(-90 38.4 247.8)">+</text>
<text x="293" y="246.9">[PCB Logo]</text>
<text x="293" y="252">[PCB Logo]</text>
<text x="293" y="257">[PCB Logo]</text>
<text x="228.3" y="265.3">VDD</text>
<text x="237.2" y="265.3">VSS</text>
</g>
</g></defs>
<g fill="#000" stroke="#000" stroke-width=".21">
<path d="M16.2 18.3v54zM40.7 19.5l.8-.8zM40.7 19.9h1.5zM41.5 18.7l.7 .8zM42.2 19.5v1.5zM16.2 18.3h50.8zM89.2 18.7h1.2zM89.2 19.9h1.2zM90.4 18.7l.4 .4zM90.4 19.9l.4 .4zM90.8 19.1v.4zM90.8 19.5l-.4 .4z"/>
<path d="M67 18.3h47.6zM137.2 19.1v1.5zM137.2 19.1l.4-.4zM137.6 18.7h.8zM138.4 18.7l.4 .4zM114.6 18.3h47.6zM184.4 18.7v2.3zM184.4 18.7h1.2zM185.6 18.7l.4 .4zM162.2 18.3h47.7zM209.9 18.3v3.2zM232.2 18.7v2.3z"/>
<path d="M232.2 19.9h.8zM232.2 18.7h1.6zM209.9 18.3h47.6zM257.5 18.3v3.2zM279.2 18.7h1.5zM279.2 19.9h.7zM257.5 18.3h47.6zM305.1 18.3v3.2zM327.7 19.1v1.5zM327.7 19.1l.4-.4zM328.1 18.7h.8zM328.9 18.7l.3 .4z"/>
<path d="M328.5 19.9h.7zM305.1 18.3h47.6zM352.7 18.3v3.2zM377.5 19.9h1.5zM379 18.7v2.3zM352.7 18.3h50.8zM19.4 21.5v50.8zM40.7 19.5v1.5zM44.2 29.8v2.5zM19.4 21.5h47.6zM67 18.3v3.2zM89.2 18.7v2.3z"/>
<path d="M89.2 21h1.2zM90.8 20.3v.3zM90.8 20.6l-.4 .4zM67 21.5h47.6zM114.6 18.3v3.2zM137.2 20.6l.4 .4zM137.6 21h.8zM138.4 21l.4-.4zM114.6 21.5h47.6zM162.2 18.3v3.2zM184.4 21h1.2zM185.6 21l.4-.4z"/>
<path d="M186 19.1v1.5zM162.2 21.5h47.7zM232.2 21h1.6zM181.3 39.9h66zM247.3 39.9v12.7zM252.4 39.9h5.1zM247.3 39.9h5.1zM209.9 21.5h47.6zM257.5 39.9h4.3zM279.2 18.7v2.3zM257.5 21.5h47.6zM327.7 20.6l.4 .4z"/>
<path d="M328.1 21h.8zM328.9 21l.3-.4zM329.2 19.9v.7zM305.1 21.5h47.6zM377.5 18.7v2.3zM352.7 21.5h47.6zM17.1 45.1v1.2zM17.1 46.3l.8-.4zM17.1 47.1l.4 .3zM17.9 45.9h.3zM18.2 45.9l.4 .4zM17.5 47.4h.7z"/>
<path d="M17.1 45.1h1.5zM18.6 46.3v.8zM18.6 47.1l-.4 .3zM49.2 47.5v2.6zM49.2 45v2.5zM49.2 45h5.1zM54.3 42.5v2.5zM54.3 45v2.5zM54.3 47.5v2.6zM56.9 55.2h5zM56.9 42.5h5zM56.9 45h5z"/>
<path d="M56.9 47.5h5zM56.9 50.1h5zM56.9 57.7h3zM54.3 42.5h2.6zM54.3 45h2.6zM54.3 47.5h2.6zM54.3 50.1h2.6zM36.5 55.2h20.4zM36.5 57.7h20.4zM61.9 54.2l2 1zM61.9 56.2l2-1zM77.2 50.1h5.1z"/>
<path d="M77.2 47.5h5.1zM77.2 45h5.1zM77.2 42.5h5.1zM77.2 55.2h5.1zM82.3 42.5h7.6zM82.3 45h7.6zM82.3 47.5h7.6zM82.3 50.1h7.6zM188.9 47.5h5.1zM188.9 50.1h5.1zM188.9 52.6h5.1zM181.3 47.5h7.6z"/>
<path d="M181.3 50.1h7.6zM181.3 52.6h7.6zM213.8 57.7h3zM213.8 55.2h3zM213.8 52.6h3zM213.8 50.1h3zM213.8 47.5h3zM216.8 55.2h7.7zM216.8 57.7h7.7zM216.8 52.6h28zM244.8 45v7.6zM244.8 45h7.6z"/>
<path d="M244.8 57.7h7.6zM247.3 52.6v12.7zM252.4 45h5.1zM252.4 52.6h5.1zM252.4 57.7h5.1zM247.3 52.6h5.1zM257.5 45h4.3zM257.5 52.6h4.3zM257.5 57.7h4.3zM262.6 42.5h5zM262.6 55.2h5zM267.6 55.2h7.7z"/>
<path d="M267.6 42.5h7.7zM389.5 55.2v2.5zM401.1 45.1v1.2zM401.1 46.3l.8-.4zM401.1 47.1l.4 .3zM401.9 45.9h.3zM402.2 45.9l.4 .4zM401.5 47.4h.7zM401.1 45.1h1.5zM402.6 46.3v.8zM402.2 47.4l.4-.3zM16.2 72.3v50.8z"/>
<path d="M16.2 72.3h3.2zM19.4 72.3v50.8zM44.2 32.3v27.9zM44.2 60.2v2.6zM44.2 62.8h12.7zM56.9 65.3h5zM56.9 60.2h5zM56.9 62.8h5zM44.2 60.2h12.7zM36.5 65.3h20.4zM64.3 64.4h2.7zM186.4 57.7v2.5z"/>
<path d="M186.4 67.9v2.5zM186.4 62.8v5.1zM188.9 62.8h3.1zM188.9 65.3h3.1zM188.9 60.2h5.1zM186.4 62.8h2.5zM186.4 60.2h2.5zM181.3 65.3h7.6zM213.8 65.3h3zM213.8 62.8h3zM213.8 60.2h3zM216.8 60.2h7.7z"/>
<path d="M216.8 62.8h28zM216.8 65.3h28zM244.8 57.7v5.1zM244.8 65.3v5.1zM244.8 70.4h7.6zM247.3 65.3h5.1zM252.4 65.3h5.1zM252.4 70.4h5.1zM257.5 65.3h4.3zM257.5 70.4h4.3zM262.6 67.9h5zM267.6 67.9h7.7z"/>
<path d="M310.8 70.4h2.6zM310.8 72.9h2.6zM310.8 75.5h2.6zM313.4 62.8h5zM313.4 65.3h5zM313.4 67.9h5zM313.4 70.4h5zM313.4 72.9h5zM313.4 75.5h5zM313.4 78h5zM310.8 62.8h2.6zM310.8 65.3h2.6z"/>
<path d="M310.8 78h2.6zM310.8 67.9h2.6zM323.5 62.8h5.1zM323.5 65.3h5.1zM323.5 67.9h5.1zM323.5 70.4h5.1zM323.5 72.9h5.1zM323.5 75.5h5.1zM323.5 78h5.1zM328.6 65.3h5.1zM328.6 67.9h5.1zM328.6 70.4h5.1z"/>
<path d="M328.6 72.9h5.1zM328.6 75.5h5.1zM371.8 60.2h2.5zM371.8 62.8h2.5zM371.8 65.3h2.5zM371.8 67.9h2.5zM371.8 70.4h2.5zM371.8 75.5h2.5zM371.8 78h2.5zM364.1 60.2h7.7zM364.1 70.4h7.7zM364.1 67.9h7.7z"/>
<path d="M364.1 65.3h7.7zM364.1 62.8h7.7zM364.1 78h7.7zM364.1 75.5h7.7zM374.3 70.4h1.3zM374.3 67.9h1.3zM374.3 65.3h1.3zM374.3 62.8h1.3zM374.3 78h1.3zM374.3 60.2h1.3zM374.3 75.5h1.3zM380.7 60.2h1.2z"/>
<path d="M381.9 60.2v2.6zM380.7 62.8h1.2zM381.9 62.8v2.5zM380.7 65.3h1.2zM381.9 65.3v2.6zM380.7 67.9h1.2zM381.9 67.9v2.5zM380.7 70.4h1.2zM381.9 60.2h2.6zM380.7 75.5h1.2zM381.9 75.5v2.5zM380.7 78h1.2z"/>
<path d="M381.9 78v2.6zM381.9 75.5h2.6zM384.5 60.2h2.5zM384.5 75.5h2.5zM387 60.2h2.5zM389.5 57.7v2.5zM389.5 60.2v15.3zM387 75.5h2.5zM400.3 21.5v50.8zM400.3 72.3h3.2zM403.5 18.3v54zM17.1 95.8h1.5z"/>
<path d="M18.2 94.6v2.4zM18.2 94.6l-1.1 1.2zM186.4 90.7v2.6zM186.4 95.8v5.1zM188.9 80.6h5.1zM188.9 83.1h5.1zM188.9 85.6h5.1zM188.9 95.8h3.1zM188.9 98.3h3.1zM188.9 93.3h5.1zM186.4 95.8h2.5zM186.4 93.3h2.5z"/>
<path d="M181.3 98.3h7.6zM181.3 80.6h7.6zM181.3 83.1h7.6zM181.3 85.6h7.6zM213.8 98.3h3zM213.8 95.8h3zM213.8 93.3h3zM213.8 90.7h3zM213.8 88.2h3zM213.8 85.6h3zM213.8 83.1h3zM213.8 80.6h3z"/>
<path d="M216.8 85.6h7.7zM216.8 88.2h7.7zM216.8 90.7h7.7zM216.8 93.3h7.7zM216.8 95.8h7.7zM216.8 98.3h7.7zM313.4 80.6h5zM313.4 83.1h5zM313.4 85.6h5zM313.4 88.2h5zM313.4 90.7h5zM313.4 93.3h5z"/>
<path d="M313.4 95.8h5zM313.4 98.3h5zM310.8 90.7h2.6zM310.8 95.8h2.6zM310.8 80.6h2.6zM310.8 83.1h2.6zM310.8 85.6h2.6zM310.8 88.2h2.6zM310.8 93.3h2.6zM323.5 80.6h5.1zM323.5 83.1h5.1zM323.5 85.6h5.1z"/>
<path d="M323.5 88.2h5.1zM323.5 90.7h5.1zM323.5 93.3h5.1zM323.5 95.8h5.1zM323.5 98.3h5.1zM328.6 95.8h5.1zM328.6 90.7h5.1zM328.6 88.2h5.1zM328.6 85.6h5.1zM328.6 80.6h5.1zM328.6 83.1h5.1zM328.6 93.3h5.1z"/>
<path d="M364.1 88.2h7.7zM364.1 90.7h7.7zM364.1 93.3h7.7zM364.1 95.8h7.7zM371.8 80.6h2.5zM371.8 85.6h2.5zM371.8 88.2h2.5zM371.8 90.7h2.5zM371.8 93.3h2.5zM371.8 95.8h2.5zM364.1 85.6h7.7zM364.1 80.6h7.7z"/>
<path d="M374.3 80.6h1.3zM374.3 95.8h1.3zM374.3 93.3h1.3zM374.3 90.7h1.3zM374.3 88.2h1.3zM374.3 85.6h1.3zM380.7 80.6h1.2zM380.7 85.6h1.2zM381.9 85.6v2.6zM380.7 88.2h1.2zM381.9 88.2v2.5zM380.7 90.7h1.2z"/>
<path d="M381.9 90.7v2.6zM380.7 93.3h1.2zM381.9 93.3v2.5zM380.7 95.8h1.2zM381.9 85.6h2.6zM384.5 85.6h2.5zM387 85.6h2.5zM389.5 75.5v10.1zM401.1 95.5h1.5zM402.2 94.4v2.3zM402.2 94.4l-1.1 1.1zM186.4 100.9v2.5z"/>
<path d="M313.4 100.9h5zM313.4 103.4h5zM313.4 105.9h5zM313.4 108.5h5zM313.4 111h5zM313.4 113.6h5zM313.4 116.1h5zM313.4 118.6h5zM310.8 113.6h2.6zM310.8 118.6h2.6zM310.8 116.1h2.6zM310.8 100.9h2.6z"/>
<path d="M310.8 108.5h2.6zM310.8 103.4h2.6zM310.8 111h2.6zM310.8 105.9h2.6zM323.5 100.9h5.1zM323.5 103.4h5.1zM323.5 105.9h5.1zM323.5 108.5h5.1zM323.5 111h5.1zM323.5 113.6h5.1zM323.5 116.1h5.1zM323.5 118.6h5.1z"/>
<path d="M328.6 100.9h5.1zM328.6 118.6h5.1zM328.6 116.1h5.1zM328.6 105.9h5.1zM328.6 108.5h5.1zM328.6 111h5.1zM328.6 113.6h5.1zM328.6 103.4h5.1zM364.1 100.9h7.7zM364.1 103.4h7.7zM364.1 105.9h7.7zM371.8 100.9h2.5z"/>
<path d="M371.8 103.4h2.5zM371.8 105.9h2.5zM371.8 111h2.5zM371.8 113.6h2.5zM371.8 116.1h2.5zM371.8 118.6h2.5zM364.1 118.6h7.7zM364.1 116.1h7.7zM364.1 113.6h7.7zM364.1 111h7.7zM374.3 105.9h1.3zM374.3 103.4h1.3z"/>
<path d="M374.3 118.6h1.3zM374.3 116.1h1.3zM374.3 113.6h1.3zM374.3 100.9h1.3zM374.3 111h1.3zM380.7 100.9h1.2zM381.9 100.9v2.5zM380.7 103.4h1.2zM381.9 103.4v2.5zM380.7 105.9h1.2zM381.9 100.9h2.6zM380.7 111h1.2z"/>
<path d="M381.9 111v2.6zM380.7 113.6h1.2zM381.9 113.6v2.5zM380.7 116.1h1.2zM381.9 116.1v2.5zM380.7 118.6h1.2zM381.9 118.6v2.6zM381.9 111h2.6zM384.5 100.9h2.5zM384.5 111h2.5zM387 100.9h2.5zM387 111h2.5z"/>
<path d="M389.5 85.6v15.3zM389.5 100.9v10.1zM16.2 123.1v50.8zM16.2 123.1h3.2zM19.4 123.1v50.8zM82.3 139h2.5zM82.3 136.4h2.5zM82.3 133.9h2.5zM82.3 131.3h2.5zM82.3 128.8h2.5zM82.3 126.3h2.5zM82.3 123.7h2.5z"/>
<path d="M74.6 133.9h7.7zM74.6 136.4h7.7zM74.6 139h7.7zM74.6 123.7h7.7zM74.6 126.3h7.7zM74.6 128.8h7.7zM74.6 131.3h7.7zM100 123.7h2.6zM100 126.3h2.6zM100 128.8h2.6zM100 131.3h2.6zM100 133.9h2.6z"/>
<path d="M100 136.4h2.6zM100 139h2.6zM102.6 123.7h7.6zM102.6 126.3h7.6zM102.6 128.8h7.6zM102.6 131.3h7.6zM102.6 133.9h7.6zM102.6 136.4h7.6zM102.6 139h7.6zM143.2 139h2.5zM143.2 136.4h2.5zM143.2 133.9h2.5z"/>
<path d="M143.2 131.3h2.5zM143.2 128.8h2.5zM143.2 126.3h2.5zM143.2 123.7h2.5zM135.6 133.9h7.6zM135.6 136.4h7.6zM135.6 139h7.6zM135.6 123.7h7.6zM135.6 126.3h7.6zM135.6 128.8h7.6zM135.6 131.3h7.6zM161 123.7h2.5z"/>
<path d="M161 126.3h2.5zM161 128.8h2.5zM161 131.3h2.5zM161 133.9h2.5zM161 136.4h2.5zM161 139h2.5zM163.5 139h7.6zM163.5 136.4h7.6zM163.5 133.9h7.6zM163.5 131.3h7.6zM163.5 123.7h7.6zM163.5 126.3h7.6z"/>
<path d="M163.5 128.8h7.6zM204.1 139h2.6zM204.1 136.4h2.6zM204.1 133.9h2.6zM204.1 131.3h2.6zM204.1 128.8h2.6zM204.1 126.3h2.6zM204.1 123.7h2.6zM196.5 133.9h7.6zM196.5 136.4h7.6zM196.5 139h7.6zM196.5 123.7h7.6z"/>
<path d="M196.5 126.3h7.6zM196.5 128.8h7.6zM196.5 131.3h7.6zM221.9 123.7h2.6zM221.9 126.3h2.6zM221.9 128.8h2.6zM221.9 131.3h2.6zM221.9 133.9h2.6zM221.9 136.4h2.6zM221.9 139h2.6zM224.5 131.3h7.6zM224.5 133.9h7.6z"/>
<path d="M224.5 136.4h7.6zM224.5 139h7.6zM224.5 126.3h7.6zM224.5 123.7h7.6zM224.5 128.8h7.6zM310.8 121.2h2.6zM313.4 121.2h5zM313.4 123.7h5zM310.8 123.7h2.6zM323.5 121.2h5.1zM323.5 123.7h5.1zM328.6 121.2h5.1z"/>
<path d="M371.8 121.2h2.5zM371.8 126.3h2.5zM371.8 128.8h2.5zM371.8 131.3h2.5zM364.1 126.3h7.7zM364.1 128.8h7.7zM364.1 131.3h7.7zM364.1 121.2h7.7zM374.3 121.2h1.3zM374.3 131.3h1.3zM374.3 128.8h1.3zM374.3 126.3h1.3z"/>
<path d="M380.7 121.2h1.2zM380.7 126.3h1.2zM381.9 126.3v2.5zM380.7 128.8h1.2zM381.9 128.8v2.5zM380.7 131.3h1.2zM381.9 126.3h2.6zM384.5 126.3h2.5zM387 126.3h2.5zM389.5 111v15.3zM400.3 72.3v50.8zM400.3 123.1h3.2z"/>
<path d="M403.5 72.3v50.8zM17.1 146.3l.4-.4zM17.5 145.9h.7zM17.1 147.9l.4 .3zM18.2 145.9l.4 .4zM17.9 147.1h.3zM18.2 147.1l.4 .4zM17.5 148.2h.7zM18.6 146.3v.4zM18.6 146.7l-.4 .4zM18.6 147.5v.4zM18.6 147.9l-.4 .3z"/>
<path d="M74.6 156.7v2.6zM74.6 159.3v2.5zM82.3 154.2h2.5zM82.3 141.5h2.5zM82.3 149.1h2.5zM82.3 151.7h2.5zM82.3 146.6h2.5zM82.3 144h2.5zM82.3 156.7h2.5zM82.3 159.3h2.5zM74.6 156.7h7.7zM74.6 159.3h7.7z"/>
<path d="M74.6 154.2h7.7zM74.6 151.7h7.7zM74.6 141.5h7.7zM74.6 144h7.7zM74.6 146.6h7.7zM74.6 149.1h7.7zM100 141.5h2.6zM102.6 141.5h7.6zM135.6 156.7v2.6zM135.6 159.3v2.5zM143.2 154.2h2.5zM143.2 141.5h2.5z"/>
<path d="M143.2 149.1h2.5zM143.2 151.7h2.5zM143.2 146.6h2.5zM143.2 144h2.5zM143.2 156.7h2.5zM143.2 159.3h2.5zM135.6 156.7h7.6zM135.6 159.3h7.6zM135.6 154.2h7.6zM135.6 151.7h7.6zM135.6 141.5h7.6zM135.6 144h7.6z"/>
<path d="M135.6 146.6h7.6zM135.6 149.1h7.6zM161 141.5h2.5zM163.5 141.5h7.6zM196.5 156.7v2.6zM196.5 159.3v2.5zM204.1 154.2h2.6zM204.1 141.5h2.6zM204.1 149.1h2.6zM204.1 151.7h2.6zM204.1 146.6h2.6zM204.1 144h2.6z"/>
<path d="M204.1 156.7h2.6zM204.1 159.3h2.6zM196.5 156.7h7.6zM196.5 159.3h7.6zM196.5 154.2h7.6zM196.5 151.7h7.6zM196.5 141.5h7.6zM196.5 144h7.6zM196.5 146.6h7.6zM196.5 149.1h7.6zM221.9 141.5h2.6zM224.5 141.5h7.6z"/>
<path d="M272.7 149.1l2.6 2.6zM272.7 151.7l2.6 2.5zM272.7 154.2l2.6 2.5zM272.7 156.7l2.6 2.6zM272.7 159.3l2.6 2.5zM275.3 151.7h10.1zM275.3 154.2h10.1zM275.3 156.7h10.1zM275.3 159.3h10.1zM285.4 151.7h5.1zM285.4 154.2h5.1zM285.4 156.7h5.1z"/>
<path d="M285.4 159.3h5.1zM290.6 148.4h.5zM290.6 146.8h.5zM290.8 146.8v1.6zM291.7 147v1.1zM291.7 148.1l.2 .3zM291.7 147l.2-.2zM291.9 148.4h.6zM291.9 146.8h.6zM292.5 148.4l.3-.3zM292.5 146.8l.3 .2zM293.3 148.1l.3 .3z"/>
<path d="M293.3 147v.3zM293.3 147.3l.3 .3zM293.6 148.4h.5zM293.3 147l.3-.2zM293.6 147.6h.8zM294.1 148.4l.3-.3zM293.6 146.8h.5zM294.4 147v1.1zM294.1 146.8l.3 .2zM305.7 159.3h5.1zM305.7 156.7h5.1zM305.7 154.2h5.1z"/>
<path d="M305.7 151.7h5.1zM310.8 151.7h12.7zM310.8 154.2h12.7zM310.8 156.7h12.7zM310.8 159.3h12.7zM326.1 149.1l-2.6 2.6zM326.1 151.7l-2.6 2.5zM323.5 156.7l2.6-2.5zM326.1 156.7l-2.6 2.6zM326.1 159.3l-2.6 2.5zM338.8 144l2.5 2.6zM338.8 146.6l2.5 2.5z"/>
<path d="M338.8 149.1l2.5 2.6zM338.8 151.7l2.5 2.5zM338.8 154.2l2.5 2.5zM338.8 156.7l2.5 2.6zM338.8 159.3l2.5 2.5zM341.3 146.6h12.7zM341.3 149.1h12.7zM341.3 151.7h12.7zM341.3 154.2h12.7zM341.3 156.7h12.7zM341.3 159.3h12.7zM354 146.6h5.1z"/>
<path d="M354 149.1h5.1zM354 151.7h5.1zM354 154.2h5.1zM354 156.7h5.1zM354 159.3h5.1zM364.1 146.6h5.1zM364.1 149.1h5.1zM364.1 151.7h5.1zM364.1 154.2h5.1zM364.1 156.7h5.1zM364.1 159.3h5.1zM369.2 146.6h15.3z"/>
<path d="M369.2 149.1h15.3zM369.2 151.7h15.3zM369.2 154.2h15.3zM369.2 156.7h15.3zM369.2 159.3h15.3zM387 144l-2.5 2.6zM384.5 149.1l2.5-2.5zM387 149.1l-2.5 2.6zM387 151.7l-2.5 2.5zM384.5 156.7l2.5-2.5zM387 156.7l-2.5 2.6zM387 159.3l-2.5 2.5z"/>
<path d="M401.1 146.3l.4-.4zM401.5 145.9h.7zM401.1 147.9l.4 .3zM402.2 145.9l.4 .4zM401.9 147.1h.3zM402.2 147.1l.4 .4zM401.5 148.2h.7zM402.6 146.3v.4zM402.2 147.1l.4-.4zM402.6 147.5v.4zM402.2 148.2l.4-.3zM16.2 173.9v50.8z"/>
<path d="M16.2 173.9h3.2zM19.4 173.9v50.8zM74.6 174.5v17.8zM74.6 161.8v2.6zM74.6 164.4v2.5zM74.6 166.9v2.5zM74.6 169.4v5.1zM77.2 177.1v12.7zM79.7 179.6v7.6zM82.3 179.6h2.5zM82.3 174.5h2.5zM82.3 177.1h2.5z"/>
<path d="M82.3 161.8h2.5zM82.3 164.4h2.5zM82.3 166.9h2.5zM82.3 169.4h2.5zM74.6 174.5h7.7zM74.6 161.8h7.7zM74.6 164.4h7.7zM74.6 166.9h7.7zM74.6 169.4h7.7zM79.7 179.6h2.6zM77.2 177.1h5.1zM87.1 178.7h3.4z"/>
<path d="M87.1 173.6h3zM87.1 176.1h3.1zM135.6 161.8v2.6zM135.6 164.4v2.5zM135.6 166.9v2.5zM135.6 169.4v5.1zM135.6 174.5v17.8zM138.1 177.1v12.7zM140.7 179.6v7.6zM143.2 179.6h2.5zM143.2 174.5h2.5zM143.2 177.1h2.5z"/>
<path d="M143.2 161.8h2.5zM143.2 164.4h2.5zM143.2 166.9h2.5zM143.2 169.4h2.5zM135.6 174.5h7.6zM135.6 161.8h7.6zM135.6 164.4h7.6zM135.6 166.9h7.6zM135.6 169.4h7.6zM140.7 179.6h2.5zM138.1 177.1h5.1zM148.1 178.7h3.4z"/>
<path d="M148.1 173.6h2.9zM148.1 176.1h3.1zM196.5 161.8v2.6zM196.5 164.4v2.5zM196.5 166.9v2.5zM196.5 169.4v5.1zM196.5 174.5v17.8zM199.1 177.1h5zM201.6 179.6h2.5zM204.1 179.6h2.6zM204.1 174.5h2.6zM204.1 177.1h2.6z"/>
<path d="M204.1 161.8h2.6zM204.1 164.4h2.6zM204.1 166.9h2.6zM204.1 169.4h2.6zM196.5 161.8h7.6zM196.5 164.4h7.6zM196.5 166.9h7.6zM196.5 169.4h7.6zM196.5 174.5h7.6zM209 178.7h3.5zM209 173.6h3zM209 176.1h3.1z"/>
<path d="M270.2 177.1h15.2zM272.7 161.8l2.6 2.6zM272.7 164.4l2.6 2.5zM272.7 166.9l2.6 2.5zM275.3 161.8h10.1zM275.3 164.4h10.1zM275.3 166.9h10.1zM275.3 169.4h10.1zM285.4 174.5h5.1zM285.4 161.8h5.1zM285.4 164.4h5.1zM285.4 166.9h5.1z"/>
<path d="M285.4 169.4h5.1zM285.4 177.1h3.1zM249.9 174.5h35.5zM305.7 169.4h5.1zM305.7 166.9h5.1zM305.7 164.4h5.1zM305.7 161.8h5.1zM310.8 161.8h12.7zM310.8 164.4h12.7zM310.8 166.9h12.7zM310.8 169.4h12.7zM323.5 164.4l2.6-2.6z"/>
<path d="M326.1 164.4l-2.6 2.5zM326.1 166.9l-2.6 2.5zM338.8 161.8l2.5 2.6zM341.3 161.8h12.7zM341.3 164.4h12.7zM354 161.8h5.1zM354 164.4h5.1zM359.1 179.6h.5zM351.5 179.6h7.6zM366.1 179.6h.6zM364.1 161.8h5.1zM364.1 164.4h5.1z"/>
<path d="M369.2 161.8h15.3zM369.2 164.4h15.3zM384.5 164.4l2.5-2.6zM400.3 123.1v50.8zM400.3 173.9h3.2zM403.5 123.1v50.8zM18.6 197.7l-1.5 1.6zM17.5 197l-.4 .4zM17.5 197h.7zM17.1 199.3h1.5zM18.6 197.4v.3zM18.2 197l.4 .4z"/>
<path d="M41.6 189.8h5.1zM34 189.8h7.6zM58.8 189.8h3.1zM61.9 189.8h15.3zM67 194.8v2.6zM67 179.6v2.5zM67 192.3v2.5zM67 192.3h7.6zM67 182.1v5.1zM67 187.2h12.7zM74.6 192.3h61zM77.2 189.8h60.9z"/>
<path d="M79.7 187.2h61zM135.6 192.3h60.9zM138.1 189.8h61zM140.7 187.2h60.9zM199.1 177.1v12.7zM201.6 179.6v7.6zM272.7 187.2l2.6 2.6zM272.7 189.8l2.6 2.5zM272.7 192.3l2.6 2.5zM272.7 194.8l2.6 2.6zM272.7 197.4l2.6 2.5zM272.7 199.9l2.6 2.6z"/>
<path d="M275.3 189.8h10.1zM275.3 192.3h10.1zM275.3 194.8h10.1zM275.3 197.4h10.1zM275.3 199.9h10.1zM285.4 189.8h5.1zM285.4 192.3h5.1zM285.4 194.8h5.1zM285.4 197.4h5.1zM285.4 199.9h5.1zM290.6 186.5h.5zM290.6 184.9h.5z"/>
<path d="M290.8 184.9v1.6zM291.7 185.1v1.1zM291.7 186.2l.2 .3zM291.9 184.9l-.2 .2zM291.9 186.5h.6zM291.9 184.9h.6zM292.8 186.2l-.3 .3zM292.5 184.9l.3 .2zM293.9 184.9l-.6 .5zM293.3 186.5h1.1zM293.9 184.9v1.6zM295 185.1v1.1z"/>
<path d="M295.2 184.9l-.2 .2zM295 186.2l1-1.1zM295.2 184.9h.6zM295 186.2l.2 .3zM295.8 184.9l.2 .2zM295.2 186.5h.6zM296 185.1v1.1zM296 186.2l-.2 .3zM305.7 199.9h5.1zM305.7 197.4h5.1zM305.7 194.8h5.1zM305.7 192.3h5.1z"/>
<path d="M305.7 189.8h5.1zM310.8 189.8h12.7zM310.8 192.3h12.7zM310.8 194.8h12.7zM310.8 197.4h12.7zM310.8 199.9h12.7zM326.1 187.2l-2.6 2.6zM326.1 189.8l-2.6 2.5zM323.5 194.8l2.6-2.5zM326.1 194.8l-2.6 2.6zM326.1 197.4l-2.6 2.5zM323.5 202.5l2.6-2.6z"/>
<path d="M338.8 189.8l2.5 2.5zM338.8 192.3l2.5 2.5zM338.8 194.8l2.5 2.6zM338.8 197.4l2.5 2.5zM338.8 199.9l2.5 2.6zM341.3 192.3h17.8zM341.3 194.8h17.8zM341.3 197.4h17.8zM341.3 199.9h17.8zM359.1 182.1h.5zM359.1 184.7h.5zM359.1 187.2h.5z"/>
<path d="M359.1 189.8h.5zM359.1 192.3h.5zM359.1 194.8h.5zM359.1 197.4h.5zM359.1 199.9h.5zM351.5 182.1h7.6zM351.5 187.2h7.6zM351.5 189.8h7.6zM351.5 184.7h7.6zM366.1 182.1h.6zM366.1 184.7h.6zM366.1 187.2h.6z"/>
<path d="M366.1 189.8h.6zM366.1 192.3h.6zM366.1 194.8h.6zM366.1 197.4h.6zM366.1 199.9h.6zM366.7 182.1h7.6zM366.7 184.7h7.6zM366.7 187.2h7.6zM366.7 189.8h17.8zM366.7 192.3h17.8zM366.7 194.8h17.8zM366.7 197.4h17.8z"/>
<path d="M366.7 199.9h17.8zM387 187.2l-2.5 2.6zM387 189.8l-2.5 2.5zM384.5 194.8l2.5-2.5zM387 194.8l-2.5 2.6zM387 197.4l-2.5 2.5zM384.5 202.5l2.5-2.6zM401.1 199l1.5-1.5zM401.5 196.7l-.4 .4zM401.5 196.7h.7zM401.1 199h1.5zM402.6 197.1v.4z"/>
<path d="M402.2 196.7l.4 .4zM204.1 210.1h5.1zM204.1 212.6h5.1zM194 212.6h10.1zM194 210.1h10.1zM214.3 210.1h5.1zM214.3 212.6h5.1zM219.4 210.1h10.1zM219.4 212.6h10.1zM249.9 174.5v38.1zM249.9 212.6h35.5zM249.9 212.6v10.2z"/>
<path d="M270.2 177.1v38.1zM270.2 215.2h15.2zM272.7 202.5l2.6 2.5zM272.7 205l2.6 2.5zM275.3 202.5h10.1zM275.3 205h10.1zM275.3 207.5h10.1zM285.4 212.6h5.1zM285.4 202.5h5.1zM285.4 205h5.1zM285.4 207.5h5.1zM285.4 215.2h3.1z"/>
<path d="M305.7 207.5h5.1zM305.7 205h5.1zM305.7 202.5h5.1zM310.8 202.5h12.7zM310.8 205h12.7zM310.8 207.5h12.7zM326.1 202.5l-2.6 2.5zM326.1 205l-2.6 2.5zM338.8 202.5l2.5 2.5zM338.8 205l2.5 2.5zM338.8 207.5l2.5 2.6zM338.8 210.1l2.5 2.5z"/>
<path d="M338.8 212.6l2.5 2.6zM338.8 215.2l2.5 2.5zM338.8 217.7l2.5 2.5zM341.3 202.5h17.8zM341.3 205h17.8zM341.3 207.5h17.8zM341.3 210.1h17.8zM341.3 212.6h17.8zM341.3 215.2h17.8zM341.3 217.7h17.8zM359.1 202.5h.5zM359.1 205h.5z"/>
<path d="M359.1 207.5h.5zM359.1 210.1h.5zM359.1 212.6h.5zM359.1 215.2h.5zM359.1 217.7h.5zM366.1 202.5h.6zM366.1 205h.6zM366.1 207.5h.6zM366.1 210.1h.6zM366.1 212.6h.6zM366.1 215.2h.6zM366.1 217.7h.6z"/>
<path d="M366.7 202.5h17.8zM366.7 205h17.8zM366.7 207.5h17.8zM366.7 210.1h17.8zM366.7 212.6h17.8zM366.7 215.2h17.8zM366.7 217.7h17.8zM387 202.5l-2.5 2.5zM387 205l-2.5 2.5zM384.5 210.1l2.5-2.6zM387 210.1l-2.5 2.5zM387 212.6l-2.5 2.6z"/>
<path d="M384.5 217.7l2.5-2.5zM384.5 220.2l2.5-2.5zM16.2 224.7v53.9zM16.2 224.7h3.2zM19.4 224.7v50.8zM28.9 235.5v2.5zM36.5 235.5v2.5zM36.5 238v5.1zM61.9 235.5v2.5zM61.9 238v5.1zM69.6 227.8v2.6zM69.6 230.4v15.2z"/>
<path d="M82.3 238h2.5zM82.3 238v7.6zM84.8 238h2.5zM87.3 238h.5zM89.4 238h.5zM89.9 238h2.5zM92.4 238h2.6zM95 227.8v2.6zM95 230.4v7.6zM95 238v7.6zM95 238h2.5zM97.5 238h2.5z"/>
<path d="M100 238h.5zM102.1 238h.5zM102.6 238h2.5zM105.1 238h2.6zM107.7 238v7.6zM206.7 227.8h5.1zM206.7 230.4h5.1zM194 227.8h12.7zM194 230.4h12.7zM216.8 227.8h5.1zM216.8 230.4h5.1zM221.9 227.8h7.6z"/>
<path d="M221.9 230.4h7.6zM247.3 222.8h2.6zM252.4 220.2h5.1zM252.4 222.8h5.1zM252.4 227.8h5.1zM252.4 230.4h5.1zM247.3 227.8h5.1zM247.3 230.4h5.1zM249.9 222.8h2.5zM247.3 220.2h5.1zM262.6 225.3h5zM267.6 225.3h2.6z"/>
<path d="M270.2 215.2v10.1zM338.8 220.2l2.5 2.6zM338.8 222.8l2.5 2.5zM338.8 225.3l2.5 2.5zM338.8 227.8l2.5 2.6zM341.3 220.2h17.8zM341.3 222.8h17.8zM341.3 225.3h17.8zM341.3 227.8h17.8zM341.3 230.4h17.8zM359.1 220.2h.5zM359.1 222.8h.5z"/>
<path d="M359.1 225.3h.5zM359.1 227.8h.5zM359.1 230.4h.5zM359.1 232.9h.5zM359.1 235.5h.5zM359.1 238h.5zM366.1 220.2h.6zM366.1 222.8h.6zM366.1 225.3h.6zM366.1 227.8h.6zM366.1 230.4h.6zM366.1 232.9h.6z"/>
<path d="M366.1 235.5h.6zM366.1 238h.6zM366.7 220.2h17.8zM366.7 225.3h17.8zM366.7 227.8h17.8zM366.7 222.8h17.8zM387 222.8l-2.5 2.5zM384.5 227.8l2.5-2.5zM387 220.2l-2.5 2.6zM400.3 173.9v50.8zM400.3 224.7h3.2zM403.5 173.9v50.8z"/>
<path d="M17.3 250.3l.8-.8zM17.3 251.9h1.6zM18.1 249.5v2.4zM28.9 255.8v5.1zM28.9 238v5.1zM36.5 250.7v2.5zM36.5 245.6v2.6zM36.5 253.2v2.6zM36.5 255.8v5.1zM28.9 255.8h7.6zM36.5 243.1h5.1zM36.5 243.1v2.5z"/>
<path d="M36.5 245.6h5.1zM28.9 243.1h7.6zM41.6 243.1h5.1zM41.6 245.6h5.1zM41.6 248.2h5.1zM41.6 250.7h5.1zM41.6 253.2h5.1zM41.6 255.8h5.1zM41.6 258.3h5.1zM36.5 253.2h5.1zM36.5 255.8h5.1zM51.8 243.1h5.1z"/>
<path d="M51.8 245.6h5.1zM51.8 248.2h5.1zM51.8 250.7h5.1zM51.8 253.2h5.1zM51.8 255.8h5.1zM51.8 258.3h5.1zM56.9 255.8h5zM56.9 253.2h5zM56.9 245.6h5zM61.9 255.8v5.1zM61.9 253.2v2.6zM56.9 243.1h5z"/>
<path d="M61.9 243.1v2.5zM69.6 245.6v7.6zM69.6 253.2v7.7zM69.6 253.2h2.5zM72.1 253.2h2.5zM72.1 245.6h2.5zM69.6 245.6h2.5zM74.6 253.2h.5zM74.6 245.6h.5zM76.7 253.2h.5zM76.7 245.6h.5zM77.2 253.2h2.5z"/>
<path d="M77.2 245.6h2.5zM79.7 253.2h2.6zM79.7 245.6h2.6zM82.3 253.2h2.5zM82.3 245.6h2.5zM82.3 245.6v7.6zM82.3 253.2v7.7zM84.8 253.2h2.5zM84.8 245.6h2.5zM87.3 253.2h.5zM87.3 245.6h.5zM89.4 253.2h.5z"/>
<path d="M89.4 245.6h.5zM89.9 253.2h2.5zM89.9 245.6h2.5zM92.4 253.2h2.6zM92.4 245.6h2.6zM95 245.6v7.6zM95 253.2v7.7zM95 253.2h2.5zM95 245.6h2.5zM97.5 253.2h2.5zM97.5 245.6h2.5zM100 253.2h.5z"/>
<path d="M100 245.6h.5zM102.1 253.2h.5zM102.1 245.6h.5zM102.6 253.2h2.5zM102.6 245.6h2.5zM105.1 245.6h2.6zM105.1 253.2h2.6zM107.7 245.6v7.6zM107.7 253.2v7.7zM128 248.2h3.1zM143.2 248.2h5.1zM148.3 248.2h2.5z"/>
<path d="M150.8 248.2v12.7zM153.3 248.2h5.1zM150.8 248.2h2.5zM170.6 248.2h3.1zM183.8 248.2v2.5zM183.8 250.7v5.1zM183.8 255.8v2.5zM183.8 258.3v5.1zM186.4 248.2h5zM186.4 250.7h5zM186.4 255.8h5zM186.4 258.3h5z"/>
<path d="M183.8 248.2h2.6zM183.8 250.7h2.6zM183.8 255.8h2.6zM183.8 258.3h2.6zM196.5 253.2h5.1zM211.8 248.2v5zM211.8 253.2v10.2zM214.3 248.2h5.1zM214.3 253.2h5.1zM211.8 248.2h2.5zM211.8 253.2h2.5zM219.4 248.2h4.3z"/>
<path d="M219.4 253.2h4.3zM224.5 250.7h5zM259.5 259.6h1zM259.5 252h1zM259.5 244.3h1zM260 259.1v1zM260 251.5v1zM260 243.8v1.1zM335.4 259.1h1.2zM335.4 257.9l.4-.3zM335.4 257.9l.4 .4zM335.8 257.6h1.2z"/>
<path d="M336.6 259.1l.4-.4zM335.8 258.3h.8zM336.6 258.3l.4 .4zM337.8 257.9v.8zM337.8 257.9l.4-.3zM337.8 258.7l.4 .4zM338.2 257.6h.7zM338.2 259.1h.7zM338.9 257.6l.4 .3zM339.3 257.9v.4zM337.8 258.3h1.5zM340.1 257.9v.8z"/>
<path d="M340.1 258.7l.4 .4zM340.1 257.9l.4-.3zM340.5 259.1h1.2zM341.7 257.6v2.3zM340.5 257.6h1.2zM342.4 257.6v1.1zM342.4 258.7l.4 .4zM342.8 259.1h1.2zM344 257.6v1.5zM344.8 257.9v.8zM344.8 257.9l.4-.3zM344.8 258.7l.4 .4z"/>
<path d="M345.2 257.6h.8zM345.2 259.1h.8zM346 257.6l.3 .3zM346.3 257.9v.4zM344.8 258.3h1.5zM347.1 257.6v1.5zM347.1 257.6h1.2zM348.3 257.6l.4 .3zM348.7 257.9v1.2zM349.5 257.9v.8zM349.5 258.7l.4 .4zM349.5 257.9l.4-.3z"/>
<path d="M349.9 259.1h1.1zM349.9 257.6h1.1zM351.8 257.9v.8zM351.8 257.9l.4-.3zM351.8 258.7l.4 .4zM352.2 257.6h.8zM352.2 259.1h.8zM353 257.6l.4 .3zM353.4 257.9v.4zM351.8 258.3h1.6zM354.1 257.6v1.5zM354.1 258.3l.8-.7z"/>
<path d="M354.9 257.6h.4zM359.1 240.5h.5zM351.5 240.5h7.6zM366.1 240.5h.6zM400.3 224.7v30.4zM401.3 248.3l.8-.8zM401.3 249.8h1.6zM402.1 247.5v2.3zM16.2 278.6h50.8zM19.4 275.5h47.6zM28.9 260.9v2.5zM36.5 260.9v2.5z"/>
<path d="M40.7 276.7v1.6zM40.7 276.7l.8-.8zM40.7 277.1h1.5zM41.5 275.9l.7 .8zM41.6 260.9h5.1zM41.6 263.4h5.1zM41.6 265.9h5.1zM42.2 276.7v1.6zM51.8 260.9h5.1zM51.8 263.4h5.1zM51.8 265.9h5.1zM61.9 260.9v2.5z"/>
<path d="M67 278.6h47.6zM67 275.5h47.6zM67 275.5v3.1zM69.6 260.9h2.5zM72.1 260.9h2.5zM74.6 260.9h.5zM76.7 260.9h.5zM77.2 260.9h2.5zM79.7 260.9h2.6zM82.3 268.5v2.5zM82.3 260.9h2.5zM82.3 260.9v7.6z"/>
<path d="M84.8 260.9h2.5zM87.3 260.9h.5zM89.4 260.9h.5zM90.7 275.9v2.4zM90.7 275.9h1.2zM90.7 277.1h1.2zM91.9 275.9l.4 .4zM91.9 277.1l.4 .4zM90.7 278.3h1.2zM92.3 276.3v.4zM92.3 276.7l-.4 .4zM92.3 277.5v.4z"/>
<path d="M92.3 277.9l-.4 .4zM89.9 260.9h2.5zM92.4 260.9h2.6zM95 260.9h2.5zM97.5 260.9h2.5zM100 260.9h.5zM102.1 260.9h.5zM102.6 260.9h2.5zM105.1 260.9h2.6zM107.7 268.5v2.5zM107.7 260.9v7.6zM114.6 278.6h47.6z"/>
<path d="M114.6 275.5h47.6zM114.6 275.5v3.1zM128 260.9h3.1zM137.5 276.3v1.6zM137.5 277.9l.4 .4zM137.5 276.3l.4-.4zM137.9 278.3h.7zM137.9 275.9h.7zM138.6 278.3l.4-.4zM138.6 275.9l.4 .4zM143.2 260.9h5.1zM150.8 263.4v2.5z"/>
<path d="M148.3 260.9h2.5zM150.8 260.9v2.5zM153.3 260.9h5.1zM150.8 260.9h2.5zM162.2 278.6h47.7zM162.2 275.5h47.7zM162.2 275.5v3.1zM170.6 260.9h3.1zM183.8 263.4v2.5zM185.7 275.9v2.4zM185.7 278.3h1.2zM186.9 278.3l.4-.4z"/>
<path d="M185.7 275.9h1.2zM187.3 276.3v1.6zM186.9 275.9l.4 .4zM209.9 278.6h47.6zM209.9 275.5h47.6zM209.9 275.5v3.1zM211.8 263.4v2.5zM224.5 260.9v2.5zM224.5 263.4v2.5zM224.5 265.9h2.5zM227 265.9h5.1zM233.2 275.9v2.4z"/>
<path d="M233.2 278.3h1.6zM233.2 277.1h.8zM233.2 275.9h1.6zM237.2 265.9h5zM242.2 265.9h2.6zM244.8 268.5v2.5zM244.8 265.9v2.6zM257.5 278.6h47.6zM257.5 275.5h47.6zM257.5 275.5v3.1zM259.5 267.2h1zM260 266.7v1z"/>
<path d="M279.9 275.9v2.4zM279.9 275.9h1.6zM279.9 277.1h.8zM305.1 278.6h47.6zM305.1 275.5h18.4zM305.1 275.5v3.1zM323.5 275.5h59.1zM323.5 265.3h76.8zM323.5 260.2h76.8zM326.4 266.9l-.4 .4zM326.4 266.9h.7zM326 268.7l.4 .3z"/>
<path d="M326.9 276.3v1.6zM326.9 277.9l.4 .4zM327.1 266.9l.3 .4zM326.7 268h.4zM327.1 268l.3 .3zM326.4 269h.7zM326.9 276.3l.4-.4zM327.3 278.3h.8zM327.4 267.3v.3zM327.4 267.6l-.3 .4zM327.4 268.3v.4zM327.4 268.7l-.3 .3z"/>
<path d="M327.3 275.9h.8zM328.1 278.3l.4-.4zM328.1 267.3v1.4zM328.1 267.3l.4-.4zM328.1 268.7l1.4-1.4zM328.1 275.9l.4 .4zM328.5 277.1v.8zM327.7 277.1h.8zM328.5 266.9h.7zM328.1 268.7l.4 .3zM329.2 266.9l.3 .4zM328.5 269h.7z"/>
<path d="M329.5 267.3v1.4zM329.5 268.7l-.3 .3zM332.3 267.6v1.4zM332.3 267.6l.7-.7zM332.3 268h1.5zM333 266.9l.8 .7zM333.8 267.6v1.4zM334.4 267.6v1.1zM334.4 268.7l.4 .3zM334.8 269h1zM335.8 267.6v1.4zM336.5 268v.7z"/>
<path d="M336.5 268.7l.4 .3zM336.9 267.6l-.4 .4zM336.9 269h1zM337.2 269.7h.4zM337.9 269.4l-.3 .3zM337.9 267.6v1.8zM336.9 267.6h1zM342.2 267.6l-1.4 1.4zM341.1 266.9l-.3 .4zM341.1 266.9h.7zM340.8 269h1.4zM342.2 267.3v.3z"/>
<path d="M341.8 266.9l.4 .4zM342.9 267.3v1.4zM342.9 267.3l.3-.4zM342.9 268.7l1.4-1.4zM343.2 266.9h.7zM342.9 268.7l.3 .3zM343.9 266.9l.4 .4zM343.2 269h.7zM344.3 267.3v1.4zM344.3 268.7l-.4 .3zM345 267.6l.7-.7zM345 269h1.4z"/>
<path d="M345.7 266.9v2.1zM347.1 267.6l.7-.7zM347.1 269h1.4zM347.8 266.9v2.1zM351.3 269l1.4-1.4zM351.6 266.9l-.3 .4zM351.6 266.9h.7zM351.3 269h1.4zM352.7 267.3v.3zM352.3 266.9l.4 .4zM352.7 278.6h50.8zM323.5 275.5h29.2z"/>
<path d="M352.7 275.5v3.1zM353.4 267.3v1.4zM353.7 266.9l-.3 .4zM353.4 268.7l1.4-1.4zM353.7 266.9h.7zM353.4 268.7l.3 .3zM354.4 266.9l.4 .4zM353.7 269h.7zM354.8 267.3v1.4zM354.8 268.7l-.4 .3zM355.5 267.6h.3zM355.5 267.6v.4z"/>
<path d="M355.5 268.7h.3zM355.5 268.7v.3zM355.8 267.6v.4zM355.5 268h.3zM355.8 268.7v.3zM355.5 269h.3zM356.9 266.9l-.4 .4zM356.9 266.9h.7zM356.5 268.7l.4 .3zM357.6 266.9l.3 .4zM357.2 268h.4zM357.6 268l.3 .3z"/>
<path d="M356.9 269h.7zM357.9 267.3v.3zM357.9 267.6l-.3 .4zM357.9 268.3v.4zM357.9 268.7l-.3 .3zM358.6 268h1.5zM359.7 266.9v2.1zM359.7 266.9l-1.1 1.1zM360.8 267.6h.3zM360.8 267.6v.4zM360.8 268.7h.3zM360.8 268.7v.3z"/>
<path d="M361.1 267.6v.4zM360.8 268h.3zM361.1 268.7v.3zM360.8 269h.3zM361.8 266.9v1.1zM361.8 268l.7-.4zM361.8 268.7l.4 .3zM362.5 267.6h.4zM362.9 267.6l.3 .4zM362.2 269h.7zM361.8 266.9h1.4zM363.2 268v.7z"/>
<path d="M363.2 268.7l-.3 .3zM363.9 268.7l.4 .3zM363.9 267.3v.3zM363.9 267.6l.4 .4zM364.3 269h.7zM364.3 266.9l-.4 .4zM364.3 268h1zM365.3 268.7l-.3 .3zM364.3 266.9h.7zM365.3 267.3v1.4zM365 266.9l.3 .4zM377.2 275.9v2.4z"/>
<path d="M377.2 277.1h1.6zM378.8 275.9v2.4zM382.6 275.5h17.7zM382.6 270.4v5.1zM382.6 270.4h17.7zM323.5 270.4h59.1zM384.6 272.5l.8-.7zM384.6 274.1h1.5zM385.4 271.8v2.3zM388.5 271.8l-1.6 2.3zM389.2 272.5l.8-.7zM389.2 274.1h1.6z"/>
<path d="M390 271.8v2.3zM400.3 270.4v5.1zM400.3 265.3v5.1zM400.3 260.2v5.1zM400.3 255.1v5.1zM403.5 224.7v53.9z"/>
<path d="M318.5 67.3l.6-.2v.3a.51 .51 0 0 0-.5 .5 .51 .51 0 0 0 .5 .5v.2a.77 .77 0 0 1-.7-.4 .77 .77 0 0 1 .1-.9z" fill-rule="evenodd"/>
<path d="M318.5 64.8l.6-.2v.2a.51 .51 0 0 0-.5 .5 .51 .51 0 0 0 .5 .5v.3a.77 .77 0 0 1-.7-.5 .77 .77 0 0 1 .1-.8z" fill-rule="evenodd"/>
<path d="M318.5 62.2l.6-.2v.3a.51 .51 0 0 0-.5 .5 .51 .51 0 0 0 .5 .5v.2a.77 .77 0 0 1-.7-.4 .77 .77 0 0 1 .1-.9z" fill-rule="evenodd"/>
<path d="M318.5 72.4l.6-.2v.2a.51 .51 0 0 0-.5 .5 .51 .51 0 0 0 .5 .5v.3a.77 .77 0 0 1-.7-.5 .77 .77 0 0 1 .1-.8z" fill-rule="evenodd"/>
<path d="M318.5 69.8l.6-.2v.3a.51 .51 0 0 0-.5 .5 .51 .51 0 0 0 .5 .5v.3a.77 .77 0 0 1-.7-.5 .77 .77 0 0 1 .1-.9z" fill-rule="evenodd"/>
<path d="M318.5 77.5l.6-.2v.2a.51 .51 0 0 0-.5 .5 .51 .51 0 0 0 .5 .5v.3a.77 .77 0 0 1-.7-.5 .77 .77 0 0 1 .1-.8z" fill-rule="evenodd"/>
<path d="M318.5 74.9l.6-.2v.3a.51 .51 0 0 0-.5 .5 .51 .51 0 0 0 .5 .5v.2a.77 .77 0 0 1-.7-.4 .77 .77 0 0 1 .1-.9z" fill-rule="evenodd"/>
<path d="M322.9 67.1a.76 .76 0 0 1 .8 .8 .76 .76 0 0 1-.8 .7v-.2a.51 .51 0 0 0 .5-.5 .51 .51 0 0 0-.5-.5z" fill-rule="evenodd"/>
<path d="M322.9 64.6a.76 .76 0 0 1 .8 .7 .76 .76 0 0 1-.8 .8v-.3a.51 .51 0 0 0 .5-.5 .51 .51 0 0 0-.5-.5z" fill-rule="evenodd"/>
<path d="M322.9 62a.76 .76 0 0 1 .8 .8 .76 .76 0 0 1-.8 .7v-.2a.51 .51 0 0 0 .5-.5 .51 .51 0 0 0-.5-.5z" fill-rule="evenodd"/>
<path d="M322.9 72.2a.76 .76 0 0 1 .8 .7 .76 .76 0 0 1-.8 .8v-.3a.51 .51 0 0 0 .5-.5 .51 .51 0 0 0-.5-.5z" fill-rule="evenodd"/>
<path d="M322.9 69.6a.76 .76 0 0 1 .8 .8 .76 .76 0 0 1-.8 .8v-.3a.51 .51 0 0 0 .5-.5 .51 .51 0 0 0-.5-.5z" fill-rule="evenodd"/>
<path d="M322.9 77.3a.76 .76 0 0 1 .8 .7 .76 .76 0 0 1-.8 .8v-.3a.51 .51 0 0 0 .5-.5 .51 .51 0 0 0-.5-.5z" fill-rule="evenodd"/>
<path d="M322.9 74.7a.76 .76 0 0 1 .8 .8 .76 .76 0 0 1-.8 .7v-.2a.51 .51 0 0 0 .5-.5 .51 .51 0 0 0-.5-.5z" fill-rule="evenodd"/>
<path d="M318.5 80l.6-.2v.3a.51 .51 0 0 0-.5 .5 .51 .51 0 0 0 .5 .5v.2a.77 .77 0 0 1-.7-.4 .77 .77 0 0 1 .1-.9z" fill-rule="evenodd"/>
<path d="M318.5 85.1l.6-.2v.2a.51 .51 0 0 0-.5 .5 .51 .51 0 0 0 .5 .5v.3a.77 .77 0 0 1-.7-.5 .77 .77 0 0 1 .1-.8z" fill-rule="evenodd"/>
<path d="M318.5 82.5l.6-.2v.3a.51 .51 0 0 0-.5 .5 .51 .51 0 0 0 .5 .5v.3a.77 .77 0 0 1-.7-.5 .77 .77 0 0 1 .1-.9z" fill-rule="evenodd"/>
<path d="M318.5 92.7l.6-.2v.3a.51 .51 0 0 0-.5 .5 .51 .51 0 0 0 .5 .5v.2a.77 .77 0 0 1-.7-.4 .77 .77 0 0 1 .1-.9z" fill-rule="evenodd"/>
<path d="M318.5 90.2l.6-.2v.2a.51 .51 0 0 0-.5 .5 .51 .51 0 0 0 .5 .5v.3a.77 .77 0 0 1-.7-.5 .77 .77 0 0 1 .1-.8z" fill-rule="evenodd"/>
<path d="M318.5 87.6l.6-.2v.3a.51 .51 0 0 0-.5 .5 .51 .51 0 0 0 .5 .5v.2a.77 .77 0 0 1-.7-.4 .77 .77 0 0 1 .1-.9z" fill-rule="evenodd"/>
<path d="M318.5 97.8l.6-.2v.2a.51 .51 0 0 0-.5 .5 .51 .51 0 0 0 .5 .5v.3a.75 .75 0 0 1-.7-.5 .75 .75 0 0 1 .1-.8z" fill-rule="evenodd"/>
<path d="M318.5 95.2l.6-.2v.3a.51 .51 0 0 0-.5 .5 .51 .51 0 0 0 .5 .5v.2a.75 .75 0 0 1-.7-.4 .75 .75 0 0 1 .1-.9z" fill-rule="evenodd"/>
<path d="M322.9 79.8a.76 .76 0 0 1 .8 .8 .76 .76 0 0 1-.8 .7v-.2a.51 .51 0 0 0 .5-.5 .51 .51 0 0 0-.5-.5z" fill-rule="evenodd"/>
<path d="M322.9 84.9a.76 .76 0 0 1 .8 .7 .76 .76 0 0 1-.8 .8v-.3a.51 .51 0 0 0 .5-.5 .51 .51 0 0 0-.5-.5z" fill-rule="evenodd"/>
<path d="M322.9 82.3a.76 .76 0 0 1 .8 .8 .76 .76 0 0 1-.8 .8v-.3a.51 .51 0 0 0 .5-.5 .51 .51 0 0 0-.5-.5z" fill-rule="evenodd"/>
<path d="M322.9 92.5a.76 .76 0 0 1 .8 .8 .76 .76 0 0 1-.8 .7v-.2a.51 .51 0 0 0 .5-.5 .51 .51 0 0 0-.5-.5z" fill-rule="evenodd"/>
<path d="M322.9 90a.76 .76 0 0 1 .8 .7 .76 .76 0 0 1-.8 .8v-.3a.51 .51 0 0 0 .5-.5 .51 .51 0 0 0-.5-.5z" fill-rule="evenodd"/>
<path d="M322.9 87.4a.76 .76 0 0 1 .8 .8 .76 .76 0 0 1-.8 .7v-.2a.51 .51 0 0 0 .5-.5 .51 .51 0 0 0-.5-.5z" fill-rule="evenodd"/>
<path d="M322.9 97.6a.76 .76 0 0 1 .8 .7 .76 .76 0 0 1-.8 .8v-.3a.51 .51 0 0 0 .5-.5 .51 .51 0 0 0-.5-.5z" fill-rule="evenodd"/>
<path d="M322.9 95a.75 .75 0 0 1 .8 .8 .75 .75 0 0 1-.8 .7v-.2a.51 .51 0 0 0 .5-.5 .51 .51 0 0 0-.5-.5z" fill-rule="evenodd"/>
<path d="M318.5 102.9l.6-.3v.3a.51 .51 0 0 0-.5 .5 .51 .51 0 0 0 .5 .5v.3a.75 .75 0 0 1-.7-.5 .75 .75 0 0 1 .1-.8z" fill-rule="evenodd"/>
<path d="M318.5 100.3l.6-.2v.2a.51 .51 0 0 0-.5 .6 .51 .51 0 0 0 .5 .5v.2a.75 .75 0 0 1-.7-.4 .75 .75 0 0 1 .1-.9z" fill-rule="evenodd"/>
<path d="M318.5 110.5l.6-.2v.2a.51 .51 0 0 0-.5 .5 .51 .51 0 0 0 .5 .5v.3a.75 .75 0 0 1-.7-.5 .75 .75 0 0 1 .1-.8z" fill-rule="evenodd"/>
<path d="M318.5 107.9l.6-.2v.3a.51 .51 0 0 0-.5 .5 .51 .51 0 0 0 .5 .5v.2a.75 .75 0 0 1-.7-.4 .75 .75 0 0 1 .1-.9z" fill-rule="evenodd"/>
<path d="M318.5 105.4l.6-.2v.2a.51 .51 0 0 0-.5 .5 .51 .51 0 0 0 .5 .5v.3a.75 .75 0 0 1-.7-.5 .75 .75 0 0 1 .1-.8z" fill-rule="evenodd"/>
<path d="M318.5 113l.6-.2v.2a.51 .51 0 0 0-.5 .6 .51 .51 0 0 0 .5 .5v.2a.75 .75 0 0 1-.7-.4 .75 .75 0 0 1 .1-.9z" fill-rule="evenodd"/>
<path d="M318.5 115.6l.6-.3v.3a.51 .51 0 0 0-.5 .5 .51 .51 0 0 0 .5 .5v.3a.75 .75 0 0 1-.7-.5 .75 .75 0 0 1 .1-.8z" fill-rule="evenodd"/>
<path d="M318.5 118.1l.6-.2v.2a.51 .51 0 0 0-.5 .5 .51 .51 0 0 0 .5 .5v.3a.75 .75 0 0 1-.7-.5 .75 .75 0 0 1 .1-.8z" fill-rule="evenodd"/>
<path d="M322.9 102.6a.76 .76 0 0 1 .8 .8 .76 .76 0 0 1-.8 .8v-.3a.51 .51 0 0 0 .5-.5 .51 .51 0 0 0-.5-.5z" fill-rule="evenodd"/>
<path d="M322.9 100.1a.76 .76 0 0 1 .8 .8 .76 .76 0 0 1-.8 .7v-.2a.51 .51 0 0 0 .5-.5 .51 .51 0 0 0-.5-.6z" fill-rule="evenodd"/>
<path d="M322.9 110.3a.76 .76 0 0 1 .8 .7 .76 .76 0 0 1-.8 .8v-.3a.51 .51 0 0 0 .5-.5 .51 .51 0 0 0-.5-.5z" fill-rule="evenodd"/>
<path d="M322.9 107.7a.76 .76 0 0 1 .8 .8 .76 .76 0 0 1-.8 .7v-.2a.51 .51 0 0 0 .5-.5 .51 .51 0 0 0-.5-.5z" fill-rule="evenodd"/>
<path d="M322.9 105.2a.76 .76 0 0 1 .8 .7 .76 .76 0 0 1-.8 .8v-.3a.51 .51 0 0 0 .5-.5 .51 .51 0 0 0-.5-.5z" fill-rule="evenodd"/>
<path d="M322.9 112.8a.76 .76 0 0 1 .8 .8 .76 .76 0 0 1-.8 .7v-.2a.51 .51 0 0 0 .5-.5 .51 .51 0 0 0-.5-.6z" fill-rule="evenodd"/>
<path d="M322.9 115.3a.76 .76 0 0 1 .8 .8 .76 .76 0 0 1-.8 .8v-.3a.51 .51 0 0 0 .5-.5 .51 .51 0 0 0-.5-.5z" fill-rule="evenodd"/>
<path d="M322.9 117.9a.76 .76 0 0 1 .8 .7 .76 .76 0 0 1-.8 .8v-.3a.51 .51 0 0 0 .5-.5 .51 .51 0 0 0-.5-.5z" fill-rule="evenodd"/>
<path d="M318.5 120.6l.6-.2v.3a.51 .51 0 0 0-.5 .5 .51 .51 0 0 0 .5 .5v.2a.75 .75 0 0 1-.7-.4 .75 .75 0 0 1 .1-.9z" fill-rule="evenodd"/>
<path d="M318.5 123.2l.6-.2v.2a.51 .51 0 0 0-.5 .5 .51 .51 0 0 0 .5 .5v.3a.75 .75 0 0 1-.7-.5 .75 .75 0 0 1 .1-.8z" fill-rule="evenodd"/>
<path d="M322.9 120.4a.76 .76 0 0 1 .8 .8 .76 .76 0 0 1-.8 .7v-.2a.51 .51 0 0 0 .5-.5 .51 .51 0 0 0-.5-.5z" fill-rule="evenodd"/>
<path d="M322.9 123a.76 .76 0 0 1 .8 .7 .76 .76 0 0 1-.8 .8v-.3a.51 .51 0 0 0 .5-.5 .51 .51 0 0 0-.5-.5z" fill-rule="evenodd"/>
<path d="M359.2 151.1l.5-.2v.2a.51 .51 0 0 0-.5 .6 .51 .51 0 0 0 .5 .5v.2a.76 .76 0 0 1-.7-.4 .76 .76 0 0 1 .2-.9z" fill-rule="evenodd"/>
<path d="M359.2 148.6l.5-.2v.2a.51 .51 0 0 0-.5 .5 .51 .51 0 0 0 .5 .5v.3a.76 .76 0 0 1-.7-.5 .76 .76 0 0 1 .2-.8z" fill-rule="evenodd"/>
<path d="M359.2 146l.5-.2v.3a.51 .51 0 0 0-.5 .5 .51 .51 0 0 0 .5 .5v.2a.76 .76 0 0 1-.7-.4 .76 .76 0 0 1 .2-.9z" fill-rule="evenodd"/>
<path d="M359.2 156.2l.5-.2v.2a.51 .51 0 0 0-.5 .5 .51 .51 0 0 0 .5 .5v.3a.76 .76 0 0 1-.7-.5 .76 .76 0 0 1 .2-.8z" fill-rule="evenodd"/>
<path d="M359.2 153.6l.5-.2v.3a.51 .51 0 0 0-.5 .5 .51 .51 0 0 0 .5 .5v.3a.76 .76 0 0 1-.7-.5 .76 .76 0 0 1 .2-.9z" fill-rule="evenodd"/>
<path d="M359.2 158.7l.5-.2v.3a.51 .51 0 0 0-.5 .5 .51 .51 0 0 0 .5 .5v.2a.76 .76 0 0 1-.7-.4 .76 .76 0 0 1 .2-.9z" fill-rule="evenodd"/>
<path d="M363.5 150.9a.76 .76 0 0 1 .8 .8 .76 .76 0 0 1-.8 .7v-.2a.51 .51 0 0 0 .5-.5 .51 .51 0 0 0-.5-.6z" fill-rule="evenodd"/>
<path d="M363.5 148.4a.76 .76 0 0 1 .8 .7 .76 .76 0 0 1-.8 .8v-.3a.51 .51 0 0 0 .5-.5 .51 .51 0 0 0-.5-.5z" fill-rule="evenodd"/>
<path d="M363.5 145.8a.76 .76 0 0 1 .8 .8 .76 .76 0 0 1-.8 .7v-.2a.51 .51 0 0 0 .5-.5 .51 .51 0 0 0-.5-.5z" fill-rule="evenodd"/>
<path d="M363.5 156a.76 .76 0 0 1 .8 .7 .76 .76 0 0 1-.8 .8v-.3a.51 .51 0 0 0 .5-.5 .51 .51 0 0 0-.5-.5z" fill-rule="evenodd"/>
<path d="M363.5 153.4a.76 .76 0 0 1 .8 .8 .76 .76 0 0 1-.8 .8v-.3a.51 .51 0 0 0 .5-.5 .51 .51 0 0 0-.5-.5z" fill-rule="evenodd"/>
<path d="M363.5 158.5a.76 .76 0 0 1 .8 .8 .76 .76 0 0 1-.8 .7v-.2a.51 .51 0 0 0 .5-.5 .51 .51 0 0 0-.5-.5z" fill-rule="evenodd"/>
<path d="M359.2 163.8l.5-.2v.2a.51 .51 0 0 0-.5 .6 .51 .51 0 0 0 .5 .5v.2a.77 .77 0 0 1-.7-.5 .77 .77 0 0 1 .2-.8z" fill-rule="evenodd"/>
<path d="M359.2 161.3l.5-.2v.2a.51 .51 0 0 0-.5 .5 .51 .51 0 0 0 .5 .5v.3a.76 .76 0 0 1-.7-.5 .76 .76 0 0 1 .2-.8z" fill-rule="evenodd"/>
<path d="M363.5 163.6a.76 .76 0 0 1 .8 .8 .76 .76 0 0 1-.8 .7v-.2a.51 .51 0 0 0 .5-.5 .51 .51 0 0 0-.5-.6z" fill-rule="evenodd"/>
<path d="M363.5 161.1a.76 .76 0 0 1 .8 .7 .76 .76 0 0 1-.8 .8v-.3a.51 .51 0 0 0 .5-.5 .51 .51 0 0 0-.5-.5z" fill-rule="evenodd"/>
<path d="M209.3 212.1l.6-.2v.2a.51 .51 0 0 0-.5 .5 .51 .51 0 0 0 .5 .5v.3a.78 .78 0 0 1-.7-.5 .78 .78 0 0 1 .1-.8z" fill-rule="evenodd"/>
<path d="M209.3 209.5l.6-.2v.3a.51 .51 0 0 0-.5 .5 .51 .51 0 0 0 .5 .5v.2a.78 .78 0 0 1-.7-.4 .78 .78 0 0 1 .1-.9z" fill-rule="evenodd"/>
<path d="M213.7 211.9a.76 .76 0 0 1 .7 .7 .76 .76 0 0 1-.7 .8v-.3a.51 .51 0 0 0 .5-.5 .51 .51 0 0 0-.5-.5z" fill-rule="evenodd"/>
<path d="M213.7 209.3a.76 .76 0 0 1 .7 .8 .76 .76 0 0 1-.7 .7v-.2a.51 .51 0 0 0 .5-.5 .51 .51 0 0 0-.5-.5z" fill-rule="evenodd"/>
<path d="M211.9 229.8l.5-.2v.3a.51 .51 0 0 0-.5 .5 .51 .51 0 0 0 .5 .5v.2a.76 .76 0 0 1-.7-.4 .76 .76 0 0 1 .2-.9z" fill-rule="evenodd"/>
<path d="M211.9 227.3l.5-.2v.2a.51 .51 0 0 0-.5 .5 .51 .51 0 0 0 .5 .5v.3a.76 .76 0 0 1-.7-.5 .76 .76 0 0 1 .2-.8z" fill-rule="evenodd"/>
<path d="M216.2 229.6a.76 .76 0 0 1 .8 .8 .76 .76 0 0 1-.8 .7v-.2a.51 .51 0 0 0 .5-.5 .51 .51 0 0 0-.5-.5z" fill-rule="evenodd"/>
<path d="M216.2 227.1a.76 .76 0 0 1 .8 .7 .76 .76 0 0 1-.8 .8v-.3a.51 .51 0 0 0 .5-.5 .51 .51 0 0 0-.5-.5z" fill-rule="evenodd"/>
<path d="M46.8 247.6l.5-.2v.2a.51 .51 0 0 0-.5 .6 .51 .51 0 0 0 .5 .5v.2a.76 .76 0 0 1-.7-.5 .76 .76 0 0 1 .2-.8z" fill-rule="evenodd"/>
<path d="M46.8 245.1l.5-.2v.2a.51 .51 0 0 0-.5 .5 .51 .51 0 0 0 .5 .5v.3a.75 .75 0 0 1-.7-.5 .75 .75 0 0 1 .2-.8z" fill-rule="evenodd"/>
<path d="M46.8 242.5l.5-.2v.3a.51 .51 0 0 0-.5 .5 .51 .51 0 0 0 .5 .5v.2a.75 .75 0 0 1-.7-.4 .75 .75 0 0 1 .2-.9z" fill-rule="evenodd"/>
<path d="M46.8 252.7l.5-.2v.2a.51 .51 0 0 0-.5 .5 .51 .51 0 0 0 .5 .5v.3a.76 .76 0 0 1-.7-.5 .76 .76 0 0 1 .2-.8z" fill-rule="evenodd"/>
<path d="M46.8 250.1l.5-.2v.3a.51 .51 0 0 0-.5 .5 .51 .51 0 0 0 .5 .5v.3a.76 .76 0 0 1-.7-.5 .76 .76 0 0 1 .2-.9z" fill-rule="evenodd"/>
<path d="M46.8 257.8l.5-.2v.2a.51 .51 0 0 0-.5 .5 .51 .51 0 0 0 .5 .5v.3a.76 .76 0 0 1-.7-.5 .76 .76 0 0 1 .2-.8z" fill-rule="evenodd"/>
<path d="M46.8 255.2l.5-.2v.3a.51 .51 0 0 0-.5 .5 .51 .51 0 0 0 .5 .5v.2a.76 .76 0 0 1-.7-.4 .76 .76 0 0 1 .2-.9z" fill-rule="evenodd"/>
<path d="M51.1 247.4a.76 .76 0 0 1 .8 .8 .76 .76 0 0 1-.8 .7v-.2a.51 .51 0 0 0 .5-.5 .51 .51 0 0 0-.5-.6z" fill-rule="evenodd"/>
<path d="M51.1 244.9a.76 .76 0 0 1 .8 .7 .76 .76 0 0 1-.8 .8v-.3a.51 .51 0 0 0 .5-.5 .51 .51 0 0 0-.5-.5z" fill-rule="evenodd"/>
<path d="M51.1 242.3a.76 .76 0 0 1 .8 .8 .76 .76 0 0 1-.8 .7v-.2a.51 .51 0 0 0 .5-.5 .51 .51 0 0 0-.5-.5z" fill-rule="evenodd"/>
<path d="M51.1 252.5a.76 .76 0 0 1 .8 .7 .76 .76 0 0 1-.8 .8v-.3a.51 .51 0 0 0 .5-.5 .51 .51 0 0 0-.5-.5z" fill-rule="evenodd"/>
<path d="M51.1 249.9a.76 .76 0 0 1 .8 .8 .76 .76 0 0 1-.8 .8v-.3a.51 .51 0 0 0 .5-.5 .51 .51 0 0 0-.5-.5z" fill-rule="evenodd"/>
<path d="M51.1 257.6a.76 .76 0 0 1 .8 .7 .76 .76 0 0 1-.8 .8v-.3a.51 .51 0 0 0 .5-.5 .51 .51 0 0 0-.5-.5z" fill-rule="evenodd"/>
<path d="M51.1 255a.76 .76 0 0 1 .8 .8 .76 .76 0 0 1-.8 .7v-.2a.51 .51 0 0 0 .5-.5 .51 .51 0 0 0-.5-.5z" fill-rule="evenodd"/>
<path d="M258 259.6h1.5l.2 .4 .3 .1v1.5a2 2 0 0 1-2-2z" fill-rule="evenodd"/>
<path d="M258 252h1.5l.2 .4 .3 .1v1.5a2 2 0 0 1-2-2z" fill-rule="evenodd"/>
<path d="M258 244.3h1.5l.2 .5 .3 .1v1.5a2 2 0 0 1-2-2.1z" fill-rule="evenodd"/>
<path d="M260 257.6a2.04 2.04 0 0 1 2.1 2h-1.6l-.2-.4-.3-.1z" fill-rule="evenodd"/>
<path d="M260 249.9a2.04 2.04 0 0 1 2.1 2.1h-1.6l-.2-.4-.3-.1z" fill-rule="evenodd"/>
<path d="M260 242.3a2.04 2.04 0 0 1 2.1 2h-1.6l-.2-.4-.3-.1z" fill-rule="evenodd"/>
<path d="M46.8 260.3l.5-.2v.2a.51 .51 0 0 0-.5 .6 .51 .51 0 0 0 .5 .5v.2a.76 .76 0 0 1-.7-.5 .76 .76 0 0 1 .2-.8z" fill-rule="evenodd"/>
<path d="M46.8 265.4l.5-.2v.2a.51 .51 0 0 0-.5 .5 .51 .51 0 0 0 .5 .5v.3a.76 .76 0 0 1-.7-.5 .76 .76 0 0 1 .2-.8z" fill-rule="evenodd"/>
<path d="M46.8 262.8l.5-.2v.3a.51 .51 0 0 0-.5 .5 .51 .51 0 0 0 .5 .5v.3a.76 .76 0 0 1-.7-.5 .76 .76 0 0 1 .2-.9z" fill-rule="evenodd"/>
<path d="M51.1 260.1a.76 .76 0 0 1 .8 .8 .76 .76 0 0 1-.8 .7v-.2a.51 .51 0 0 0 .5-.5 .51 .51 0 0 0-.5-.6z" fill-rule="evenodd"/>
<path d="M51.1 265.2a.76 .76 0 0 1 .8 .7 .76 .76 0 0 1-.8 .8v-.3a.51 .51 0 0 0 .5-.5 .51 .51 0 0 0-.5-.5z" fill-rule="evenodd"/>
<path d="M51.1 262.6a.76 .76 0 0 1 .8 .8 .76 .76 0 0 1-.8 .8v-.3a.51 .51 0 0 0 .5-.5 .51 .51 0 0 0-.5-.5z" fill-rule="evenodd"/>
<path d="M258 267.2h1.5l.2 .4 .3 .1v1.5a2 2 0 0 1-2-2z" fill-rule="evenodd"/>
<path d="M260 265.2a2.04 2.04 0 0 1 2.1 2h-1.6l-.2-.4-.3-.1z" fill-rule="evenodd"/>
<circle cx="247.3" cy="39.9" r=".51"/>
<circle cx="54.3" cy="47.5" r=".51"/>
<circle cx="54.3" cy="45" r=".51"/>
<circle cx="247.3" cy="52.6" r=".51"/>
<circle cx="44.2" cy="60.2" r=".51"/>
<circle cx="389.5" cy="60.2" r=".51"/>
<circle cx="389.5" cy="75.5" r=".51"/>
<circle cx="389.5" cy="85.6" r=".51"/>
<circle cx="389.5" cy="100.9" r=".51"/>
<circle cx="389.5" cy="111" r=".51"/>
<circle cx="74.6" cy="159.3" r=".51"/>
<circle cx="135.6" cy="159.3" r=".51"/>
<circle cx="196.5" cy="159.3" r=".51"/>
<circle cx="74.6" cy="161.8" r=".51"/>
<circle cx="74.6" cy="169.4" r=".51"/>
<circle cx="74.6" cy="174.5" r=".51"/>
<circle cx="74.6" cy="166.9" r=".51"/>
<circle cx="74.6" cy="164.4" r=".51"/>
<circle cx="135.6" cy="174.5" r=".51"/>
<circle cx="135.6" cy="161.8" r=".51"/>
<circle cx="135.6" cy="169.4" r=".51"/>
<circle cx="135.6" cy="164.4" r=".51"/>
<circle cx="135.6" cy="166.9" r=".51"/>
<circle cx="196.5" cy="174.5" r=".51"/>
<circle cx="196.5" cy="169.4" r=".51"/>
<circle cx="196.5" cy="164.4" r=".51"/>
<circle cx="196.5" cy="166.9" r=".51"/>
<circle cx="196.5" cy="161.8" r=".51"/>
<circle cx="74.6" cy="192.3" r=".51"/>
<circle cx="77.2" cy="189.8" r=".51"/>
<circle cx="79.7" cy="187.2" r=".51"/>
<circle cx="135.6" cy="192.3" r=".51"/>
<circle cx="138.1" cy="189.8" r=".51"/>
<circle cx="140.7" cy="187.2" r=".51"/>
<circle cx="249.9" cy="212.6" r=".51"/>
<circle cx="270.2" cy="215.2" r=".51"/>
<circle cx="95" cy="238" r=".51"/>
<circle cx="249.9" cy="222.8" r=".51"/>
<circle cx="36.5" cy="255.8" r=".51"/>
<circle cx="36.5" cy="243.1" r=".51"/>
<circle cx="36.5" cy="245.6" r=".51"/>
<circle cx="36.5" cy="253.2" r=".51"/>
<circle cx="61.9" cy="243.1" r=".51"/>
<circle cx="61.9" cy="255.8" r=".51"/>
<circle cx="69.6" cy="245.6" r=".51"/>
<circle cx="69.6" cy="253.2" r=".51"/>
<circle cx="82.3" cy="253.2" r=".51"/>
<circle cx="82.3" cy="245.6" r=".51"/>
<circle cx="95" cy="245.6" r=".51"/>
<circle cx="95" cy="253.2" r=".51"/>
<circle cx="107.7" cy="245.6" r=".51"/>
<circle cx="107.7" cy="253.2" r=".51"/>
<circle cx="150.8" cy="248.2" r=".51"/>
<circle cx="183.8" cy="250.7" r=".51"/>
<circle cx="183.8" cy="258.3" r=".51"/>
<circle cx="183.8" cy="255.8" r=".51"/>
<circle cx="211.8" cy="253.2" r=".51"/>
<circle cx="82.3" cy="260.9" r=".51"/>
<circle cx="95" cy="260.9" r=".51"/>
<circle cx="107.7" cy="260.9" r=".51"/>
<circle cx="150.8" cy="260.9" r=".51"/>
</g>
<path d="M305.1 255.1h18.4zM323.5 255.1h76.8zM305.1 255.1v20.4zM323.5 270.4v5.1zM323.5 265.3v5.1zM323.5 260.2v5.1zM323.5 255.1v5.1z" fill="#000" stroke="#000" stroke-width=".61"/>
<g fill="none" stroke="#000" stroke-width=".21">
<circle cx="60.9" cy="57.7" r=".99"/>
<circle cx="212.8" cy="55.2" r="1"/>
<circle cx="212.8" cy="47.5" r="1"/>
<circle cx="212.8" cy="57.7" r="1"/>
<circle cx="212.8" cy="52.6" r="1"/>
<circle cx="212.8" cy="50.1" r="1"/>
<circle cx="193" cy="65.3" r=".99"/>
<circle cx="193" cy="62.8" r=".99"/>
<circle cx="212.8" cy="65.3" r="1"/>
<circle cx="212.8" cy="60.2" r="1"/>
<circle cx="212.8" cy="62.8" r="1"/>
<circle cx="193" cy="95.8" r=".99"/>
<circle cx="193" cy="98.3" r=".99"/>
<circle cx="212.8" cy="90.7" r="1"/>
<circle cx="212.8" cy="93.3" r="1"/>
<circle cx="212.8" cy="95.8" r="1"/>
<circle cx="212.8" cy="98.3" r="1"/>
<circle cx="212.8" cy="88.2" r="1"/>
<circle cx="212.8" cy="85.6" r="1"/>
<circle cx="212.8" cy="80.6" r="1"/>
<circle cx="212.8" cy="83.1" r="1"/>
<circle cx="289.5" cy="177.1" r="1"/>
<circle cx="360.6" cy="179.6" r="1"/>
<circle cx="365.1" cy="179.6" r="1"/>
<circle cx="57.8" cy="189.8" r=".99"/>
<circle cx="360.6" cy="182.1" r="1"/>
<circle cx="360.6" cy="184.7" r="1"/>
<circle cx="360.6" cy="189.8" r="1"/>
<circle cx="360.6" cy="192.3" r="1"/>
<circle cx="360.6" cy="197.4" r="1"/>
<circle cx="360.6" cy="199.9" r="1"/>
<circle cx="360.6" cy="187.2" r="1"/>
<circle cx="360.6" cy="194.8" r="1"/>
<circle cx="365.1" cy="187.2" r="1"/>
<circle cx="365.1" cy="194.8" r="1"/>
<circle cx="365.1" cy="192.3" r="1"/>
<circle cx="365.1" cy="189.8" r="1"/>
<circle cx="365.1" cy="197.4" r="1"/>
<circle cx="365.1" cy="182.1" r="1"/>
<circle cx="365.1" cy="199.9" r="1"/>
<circle cx="365.1" cy="184.7" r="1"/>
<circle cx="289.5" cy="215.2" r="1"/>
<circle cx="360.6" cy="212.6" r="1"/>
<circle cx="360.6" cy="215.2" r="1"/>
<circle cx="360.6" cy="217.7" r="1"/>
<circle cx="360.6" cy="205" r="1"/>
<circle cx="360.6" cy="202.5" r="1"/>
<circle cx="360.6" cy="207.5" r="1"/>
<circle cx="360.6" cy="210.1" r="1"/>
<circle cx="365.1" cy="217.7" r="1"/>
<circle cx="365.1" cy="215.2" r="1"/>
<circle cx="365.1" cy="212.6" r="1"/>
<circle cx="365.1" cy="202.5" r="1"/>
<circle cx="365.1" cy="210.1" r="1"/>
<circle cx="365.1" cy="207.5" r="1"/>
<circle cx="365.1" cy="205" r="1"/>
<circle cx="360.6" cy="230.4" r="1"/>
<circle cx="360.6" cy="235.5" r="1"/>
<circle cx="360.6" cy="220.2" r="1"/>
<circle cx="360.6" cy="222.8" r="1"/>
<circle cx="360.6" cy="238" r="1"/>
<circle cx="360.6" cy="227.8" r="1"/>
<circle cx="360.6" cy="232.9" r="1"/>
<circle cx="360.6" cy="225.3" r="1"/>
<circle cx="365.1" cy="230.4" r="1"/>
<circle cx="365.1" cy="222.8" r="1"/>
<circle cx="365.1" cy="238" r="1"/>
<circle cx="365.1" cy="227.8" r="1"/>
<circle cx="365.1" cy="235.5" r="1"/>
<circle cx="365.1" cy="225.3" r="1"/>
<circle cx="365.1" cy="232.9" r="1"/>
<circle cx="365.1" cy="220.2" r="1"/>
<circle cx="132.1" cy="248.2" r=".99"/>
<circle cx="169.6" cy="248.2" r=".99"/>
<circle cx="260" cy="252" r="2.03"/>
<circle cx="260" cy="244.3" r="2.03"/>
<circle cx="260" cy="259.6" r="2.03"/>
<circle cx="260" cy="259.6" r=".51"/>
<circle cx="260" cy="244.3" r=".51"/>
<circle cx="260" cy="252" r=".51"/>
<circle cx="360.6" cy="240.5" r="1"/>
<circle cx="365.1" cy="240.5" r="1"/>
<circle cx="132.1" cy="260.9" r=".99"/>
<circle cx="169.6" cy="260.9" r=".99"/>
<circle cx="260" cy="267.2" r="2.03"/>
<circle cx="260" cy="267.2" r=".51"/>
</g>
<g fill="#000" stroke="#000" stroke-width=".42">
<path d="M61.9 39.9v28zM61.9 39.9h15.3zM257.5 37.4v10.1zM194 45v22.9zM194 45h17.8zM257.5 50.1v10.1zM374.3 57.7h8.9zM374.3 57.7v15.2zM383.2 57.7v15.2zM61.9 67.9h15.3zM77.2 39.9v28zM194 78v22.9z"/>
<path d="M194 67.9h17.8zM194 78h17.8zM211.8 45v22.9zM257.5 62.8v10.1zM317.2 60.2h7.6zM317.2 60.2v66.1zM374.3 72.9h8.9zM374.3 72.9v10.2zM383.2 72.9v10.2zM374.3 83.1h8.9zM374.3 83.1v15.2zM374.3 98.3h8.9z"/>
<path d="M374.3 98.3v10.2zM383.2 83.1v15.2zM383.2 98.3v10.2zM194 100.9h17.8zM211.8 78v22.9zM374.3 108.5h8.9zM374.3 108.5v15.2zM383.2 108.5v15.2zM84.8 121.2v60.9zM84.8 121.2h15.2zM145.7 121.2v60.9zM145.7 121.2h15.3z"/>
<path d="M206.7 121.2v60.9zM206.7 121.2h15.2zM324.8 60.2v66.1zM317.2 126.3h7.6zM374.3 123.7h8.9zM374.3 123.7v10.2zM383.2 123.7v10.2zM374.3 133.9h8.9zM290.5 149.1v30.5zM290.5 149.1h15.2zM357.8 144h7.6zM357.8 144v22.9z"/>
<path d="M290.5 179.6h15.2zM305.7 149.1v30.5zM355.3 177.1v66zM365.4 144v22.9zM357.8 166.9h7.6zM355.3 177.1h15.2zM46.7 184.7l10.2 5.1zM46.7 184.7v10.1zM46.7 194.8l10.2-5zM84.8 182.1h15.2zM100 121.2v60.9zM145.7 182.1h15.3z"/>
<path d="M161 121.2v60.9zM206.7 182.1h15.2zM221.9 121.2v60.9zM290.5 187.2v30.5zM290.5 187.2h15.2zM208 207.5h7.6zM208 207.5v7.7zM215.6 207.5v7.7zM208 215.2h7.6zM257.5 217.7v15.2zM290.5 217.7h15.2zM305.7 187.2v30.5z"/>
<path d="M210.5 225.3h7.6zM210.5 225.3v7.6zM218.1 225.3v7.6zM210.5 232.9h7.6zM262.6 222.8v5zM45.4 240.5h7.6zM53 240.5v28zM133 248.2l10.2-5.1zM133 248.2l10.2 5zM143.2 243.1v10.1zM143.2 255.8v10.1zM158.4 243.1l10.2 5.1z"/>
<path d="M158.4 243.1v10.1zM158.4 255.8l10.2 5.1zM158.4 253.2l10.2-5zM191.4 245.6v15.3zM196.5 250.7v5.1zM219.4 245.6v10.2zM355.3 243.1h15.2zM370.5 177.1v66zM45.4 240.5v28zM45.4 268.5h7.6zM133 260.9l10.2-5.1zM133 260.9l10.2 5z"/>
<path d="M158.4 255.8v10.1zM158.4 265.9l10.2-5z"/>
</g>
<g fill="#000" stroke="#000" stroke-width=".28">
<path d="M44.2 29.8l-1.3 1.9zM44.2 29.8l1.2 1.9zM47.3 50.1h3.8zM186.4 57.7l-1.3 1.9zM186.4 57.7l1.2 1.9zM375.6 59.5v.7zM375.6 59.5h5.1zM389.5 55.2l-1.2 1.9zM389.5 55.2l1.3 1.9zM184.5 70.4h3.8zM375.6 61h5.1zM375.6 60.2v.8z"/>
<path d="M375.6 62.8v.7zM375.6 62v.8zM375.6 63.5h5.1zM375.6 66.1h5.1zM375.6 68.6h5.1zM375.6 71.2h5.1zM375.6 65.3v.8zM375.6 67.9v.7zM375.6 70.4v.8zM375.6 64.6v.7zM375.6 67.1v.8zM375.6 69.6v.8z"/>
<path d="M375.6 76.2h5.1zM375.6 74.7v.8zM375.6 75.5v.7zM375.6 78v.8zM375.6 77.3v.7zM375.6 78.8h5.1zM375.6 79.8v.8zM380.7 60.2v.8zM380.7 59.5v.7zM380.7 62.8v.7zM380.7 62v.8zM375.6 62h5.1z"/>
<path d="M375.6 64.6h5.1zM375.6 67.1h5.1zM375.6 69.6h5.1zM380.7 65.3v.8zM380.7 67.9v.7zM380.7 70.4v.8zM380.7 64.6v.7zM380.7 67.1v.8zM380.7 69.6v.8zM375.6 74.7h5.1zM380.7 75.5v.7zM380.7 74.7v.8z"/>
<path d="M380.7 78v.8zM380.7 77.3v.7zM375.6 77.3h5.1zM375.6 79.8h5.1zM186.4 90.7l-1.3 1.9zM186.4 90.7l1.2 1.9zM375.6 81.3h5.1zM375.6 80.6v.7zM375.6 86.4h5.1zM375.6 84.9v.7zM375.6 85.6v.8zM375.6 88.2v.7z"/>
<path d="M375.6 87.4v.8zM375.6 88.9h5.1zM375.6 91.5h5.1zM375.6 94h5.1zM375.6 96.5h5.1zM375.6 90.7v.8zM375.6 93.3v.7zM375.6 95.8v.7zM375.6 90v.7zM375.6 92.5v.8zM375.6 95v.8zM380.7 80.6v.7z"/>
<path d="M380.7 79.8v.8zM375.6 84.9h5.1zM380.7 85.6v.8zM380.7 84.9v.7zM380.7 88.2v.7zM380.7 87.4v.8zM375.6 87.4h5.1zM375.6 90h5.1zM375.6 92.5h5.1zM375.6 95h5.1zM380.7 90.7v.8zM380.7 93.3v.7z"/>
<path d="M380.7 95.8v.7zM380.7 90v.7zM380.7 92.5v.8zM380.7 95v.8zM184.5 103.4h3.8zM375.6 101.6h5.1zM375.6 100.1v.8zM375.6 100.9v.7zM375.6 103.4v.8zM375.6 102.6v.8zM375.6 104.2h5.1zM375.6 106.7h5.1z"/>
<path d="M375.6 105.9v.8zM375.6 105.2v.7zM375.6 111.8h5.1zM375.6 110.3v.7zM375.6 111v.8zM375.6 113.6v.7zM375.6 112.8v.8zM375.6 114.3h5.1zM375.6 116.9h5.1zM375.6 119.4h5.1zM375.6 116.1v.8zM375.6 118.6v.8z"/>
<path d="M375.6 115.3v.8zM375.6 117.9v.7zM375.6 100.1h5.1zM380.7 100.9v.7zM380.7 100.1v.8zM380.7 103.4v.8zM380.7 102.6v.8zM375.6 102.6h5.1zM375.6 105.2h5.1zM380.7 105.9v.8zM380.7 105.2v.7zM375.6 110.3h5.1z"/>
<path d="M380.7 111v.8zM380.7 110.3v.7zM380.7 113.6v.7zM380.7 112.8v.8zM375.6 112.8h5.1zM375.6 115.3h5.1zM375.6 117.9h5.1zM380.7 116.1v.8zM380.7 118.6v.8zM380.7 115.3v.8zM380.7 117.9v.7zM375.6 121.9h5.1z"/>
<path d="M375.6 121.2v.7zM375.6 120.4v.8zM375.6 127h5.1zM375.6 125.5v.8zM375.6 126.3v.7zM375.6 128.8v.8zM375.6 128v.8zM375.6 129.6h5.1zM375.6 132.1h5.1zM375.6 131.3v.8zM375.6 130.6v.7zM375.6 120.4h5.1z"/>
<path d="M380.7 121.2v.7zM380.7 120.4v.8zM375.6 125.5h5.1zM380.7 126.3v.7zM380.7 125.5v.8zM380.7 128.8v.8zM380.7 128v.8zM375.6 128h5.1zM375.6 130.6h5.1zM380.7 131.3v.8zM380.7 130.6v.7zM67 179.6l-1.3 1.9z"/>
<path d="M65.1 197.4h3.8zM67 179.6l1.3 1.9zM28.9 235.5l-1.3 1.9zM28.9 234.2l-1.3 3.2zM28.9 235.5l1.3 1.9zM28.9 234.2l1.3 3.2zM36.5 235.5l-1.2 1.9zM36.5 235.5l1.3 1.9zM61.9 235.5l-1.2 1.9zM61.9 235.5l1.3 1.9zM69.6 227.8l-1.3 1.9zM69.6 227.8l1.2 1.9z"/>
<path d="M95 227.8l-1.3 1.9zM95 227.8l1.2 1.9zM35 248.2v.8zM35 249h3.1zM38.1 248.2v.8zM35 248.2h3.1zM27.6 261.5l1.3 1.9zM27.6 261.5l1.3 3.2zM30.2 261.5l-1.3 1.9zM30.2 261.5l-1.3 3.2zM34.6 263.4h3.8zM60 263.4h3.8z"/>
<path d="M80.3 271h3.9zM105.7 271h3.9zM148.9 265.9h3.8zM181.9 265.9h3.8zM209.9 265.9h3.8zM224.5 260.9l-1.3 1.9zM224.5 260.9l1.2 1.9zM242.9 271h3.8z"/>
</g>
<g fill="#000" stroke="#000" stroke-width=".21">
<path d="M87.8 236h.5v4h-.5zM88.9 236h.5v4h-.5zM100.5 236h.5v4h-.5zM101.6 236h.5v4h-.5zM34.9 249.8h3.3v.9h-3.3zM75.1 258.8h.5v4.1h-.5zM75.1 251.2h.5v4.1h-.5zM75.1 243.6h.5v4h-.5zM76.2 258.8h.5v4.1h-.5zM76.2 251.2h.5v4.1h-.5zM76.2 243.6h.5v4h-.5zM87.8 258.8h.5v4.1h-.5z"/>
<path d="M87.8 251.2h.5v4.1h-.5zM87.8 243.6h.5v4h-.5zM88.9 258.8h.5v4.1h-.5zM88.9 251.2h.5v4.1h-.5zM88.9 243.6h.5v4h-.5zM100.5 258.8h.5v4.1h-.5zM100.5 251.2h.5v4.1h-.5zM100.5 243.6h.5v4h-.5zM101.6 258.8h.5v4.1h-.5zM101.6 251.2h.5v4.1h-.5zM101.6 243.6h.5v4h-.5z"/>
</g>
<g fill="none" stroke="#000" stroke-width=".42">
<path d="M257.5 37.4a5.1 5.1 0 0 1 5.1 5.1 5.1 5.1 0 0 1-5.1 5M257.5 50.1a5.1 5.1 0 0 1 5.1 5.1 5.1 5.1 0 0 1-5.1 5M257.5 62.8a5.1 5.1 0 0 1 5.1 5.1 5.1 5.1 0 0 1-5.1 5M257.5 217.7a5.1 5.1 0 0 1 5.1 5.1M262.6 227.8a5 5 0 0 1-5.1 5.1M191.4 245.6a5.1 5.1 0 0 1 5.1 5.1M196.5 255.8a5.1 5.1 0 0 1-5.1 5.1M219.4 245.6a5.1 5.1 0 0 1 5.1 5.1 5.1 5.1 0 0 1-5.1 5.1"/>
<circle cx="381.9" cy="78" r=".25"/>
<circle cx="381.9" cy="60.2" r=".25"/>
<circle cx="381.9" cy="67.9" r=".25"/>
<circle cx="381.9" cy="65.3" r=".25"/>
<circle cx="381.9" cy="62.8" r=".25"/>
<circle cx="381.9" cy="75.5" r=".25"/>
<circle cx="381.9" cy="93.3" r=".25"/>
<circle cx="381.9" cy="85.6" r=".25"/>
<circle cx="381.9" cy="90.7" r=".25"/>
<circle cx="381.9" cy="88.2" r=".25"/>
<circle cx="381.9" cy="103.4" r=".25"/>
<circle cx="381.9" cy="118.6" r=".25"/>
<circle cx="381.9" cy="111" r=".25"/>
<circle cx="381.9" cy="100.9" r=".25"/>
<circle cx="381.9" cy="116.1" r=".25"/>
<circle cx="381.9" cy="113.6" r=".25"/>
<circle cx="381.9" cy="128.8" r=".25"/>
<circle cx="381.9" cy="126.3" r=".25"/>
</g>
<path d="M272.7 149.1v58.4zM326.1 149.1v58.4zM338.8 141.5v25.4zM387 141.5v25.4zM338.8 189.8v38zM387 187.2v38.1z" fill="#000" stroke="#000" stroke-width=".76"/>
<use href="#words"/>
</svg>
